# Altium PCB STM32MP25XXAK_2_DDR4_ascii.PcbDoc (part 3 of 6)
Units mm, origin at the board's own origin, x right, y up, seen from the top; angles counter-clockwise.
Board outline 120 x 79.6 mm, 4 copper layers (Top Layer, Signal Layer 1, Signal Layer 2, Bottom Layer), stack 1.614 mm thick; 243 components, 152 nets, 1304 pads, 784 vias.
Unrouted connection lines stored in the file: 6.

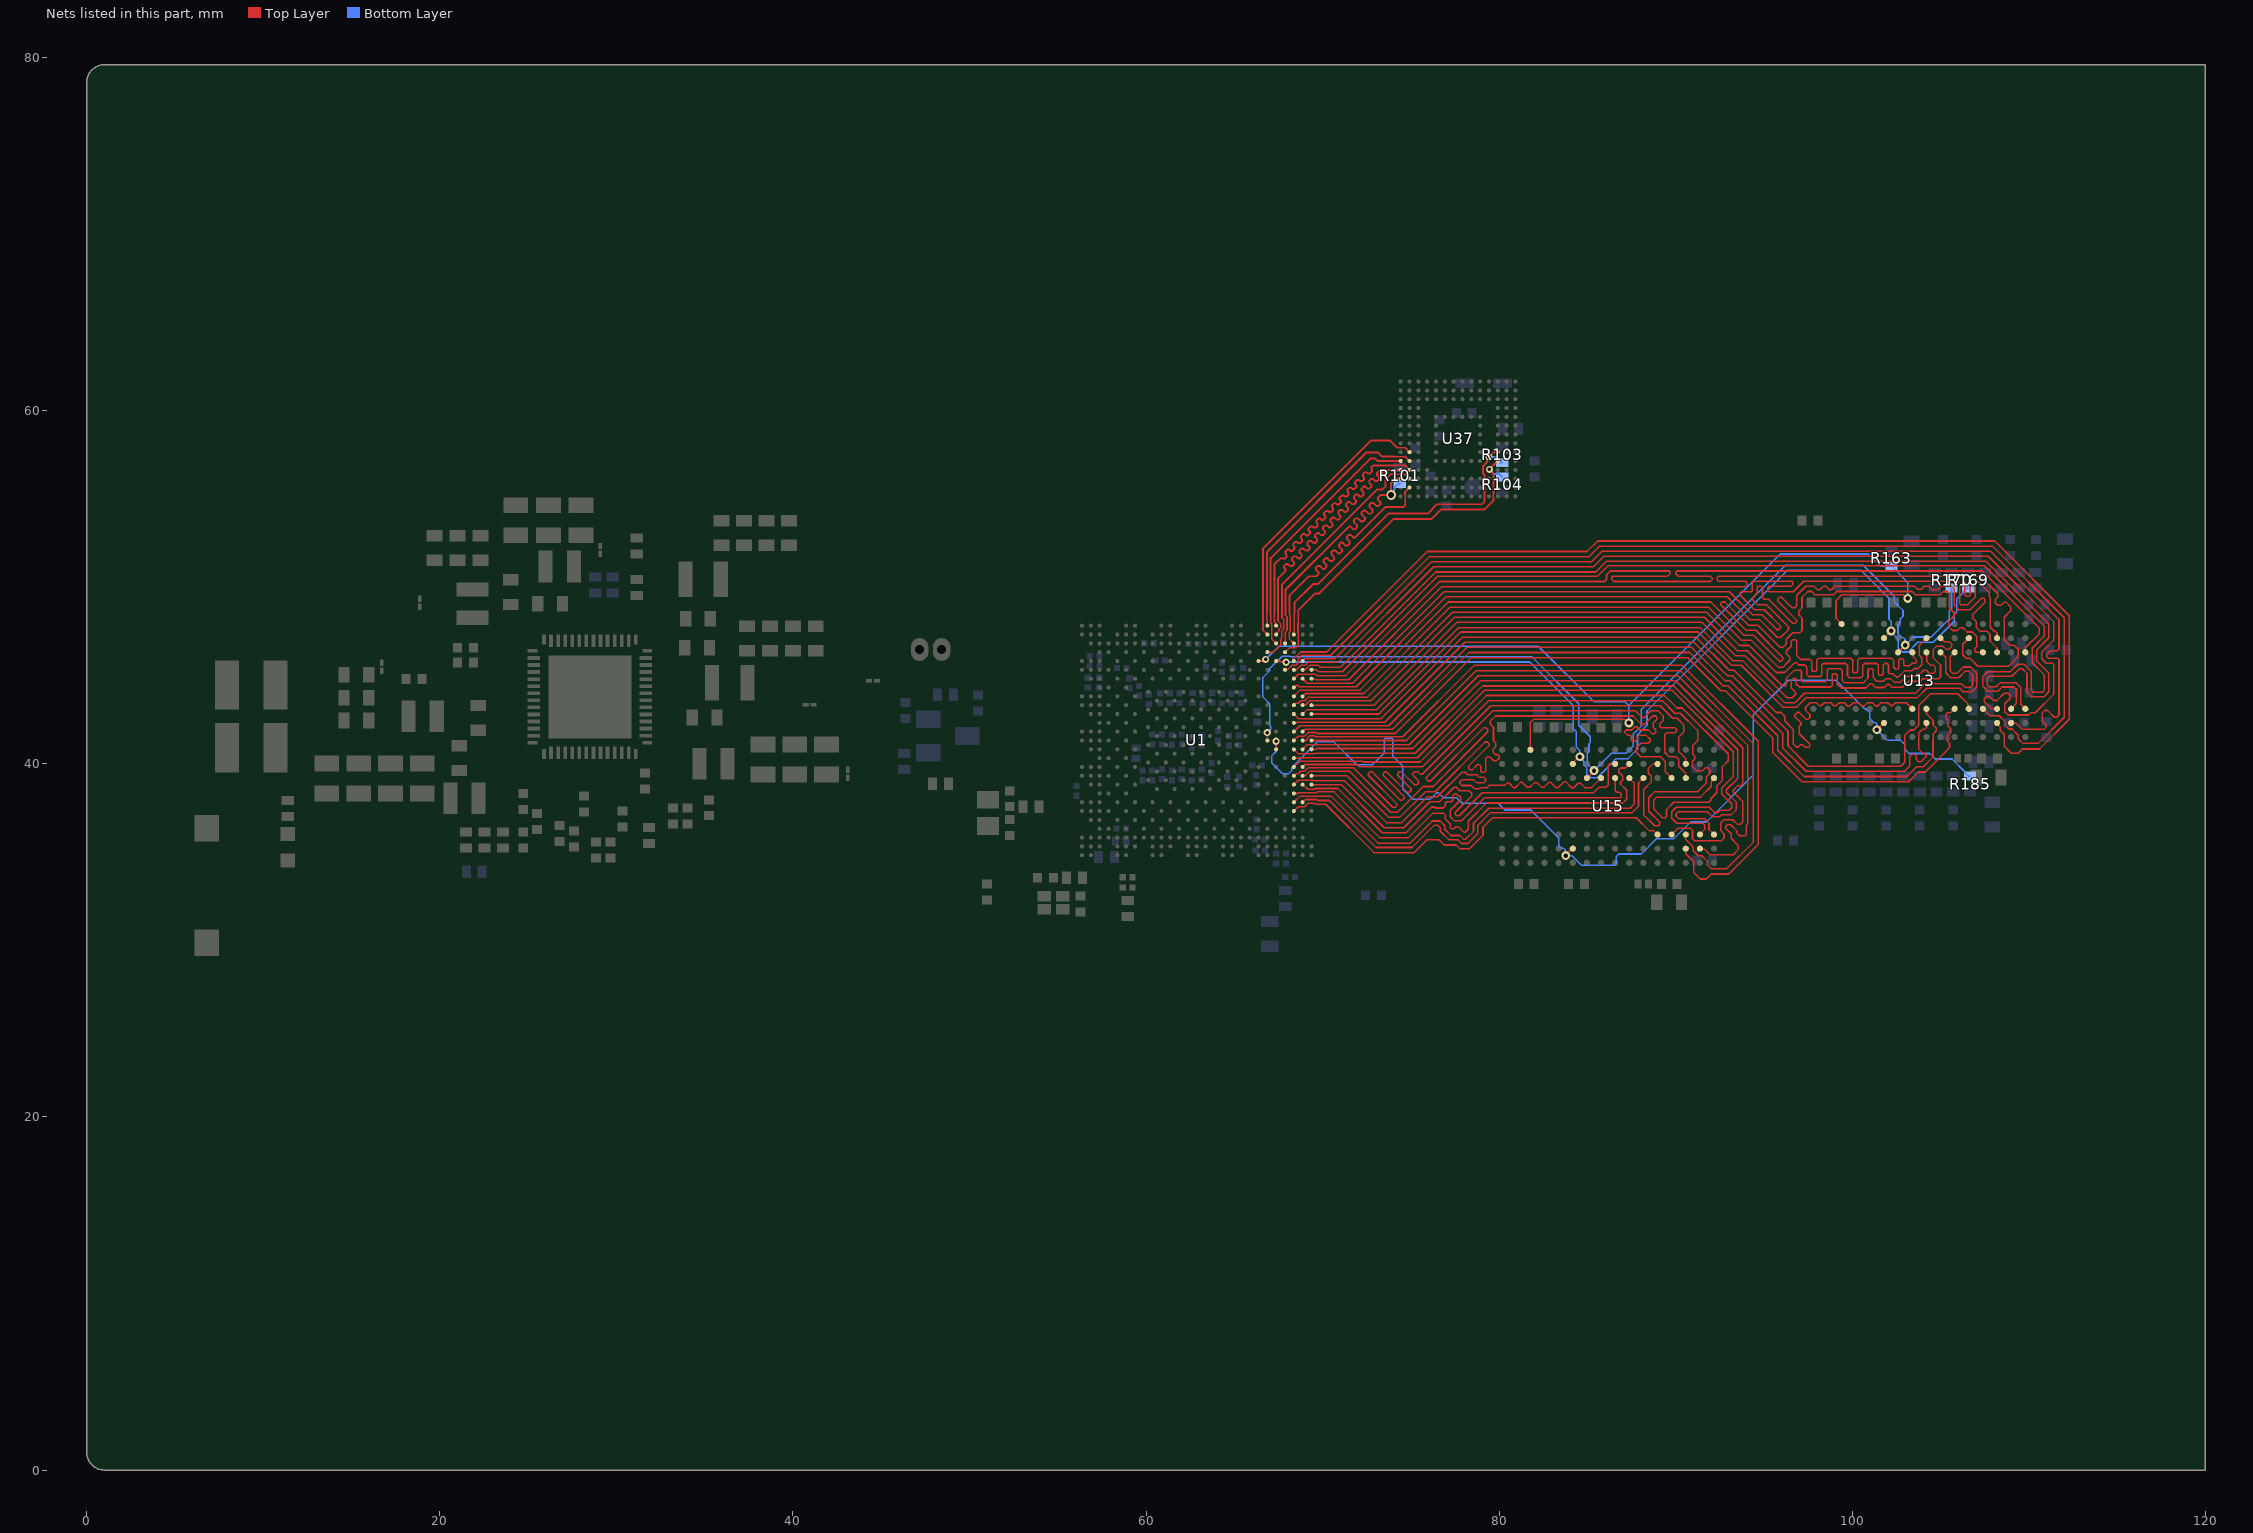
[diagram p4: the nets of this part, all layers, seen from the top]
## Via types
v1: diameter 0.55, hole 0.35, Top Layer to Bottom Layer, 256 vias
v2: diameter 0.4, hole 0.2, Top Layer to Bottom Layer, tented both sides, 235 vias
v3: diameter 0.5, hole 0.2, Top Layer to Bottom Layer, 146 vias
v4: diameter 0.5, hole 0.25, Top Layer to Bottom Layer, 143 vias
v5: diameter 0.5, hole 0.25, Top Layer to Bottom Layer, tented both sides, 4 vias

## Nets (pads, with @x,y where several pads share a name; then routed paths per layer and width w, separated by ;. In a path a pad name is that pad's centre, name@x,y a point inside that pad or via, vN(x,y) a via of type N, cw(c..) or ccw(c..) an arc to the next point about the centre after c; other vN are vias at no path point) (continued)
DDR_DQ4: U1.W25 U15.J3 | length 24.8
  Top Layer w0.09: U1.W25@68.375,38.825 68.625,39.075 69.479,39.075 69.503,39.05 71.246,39.05 73.622,36.674 74.485,36.674 75.948,38.137 76.504,38.137 77.893,39.527 78.085,39.527 78.231,39.381 78.741,39.381 78.891,39.231 79.151,39.231 79.229,39.153 79.229,39.006 79.164,38.941 78.725,38.941 78.576,39.09 77.892,39.09 77.783,38.981 77.783,38.887 77.896,38.773 78.424,38.773 78.613,38.585 78.857,38.585 78.923,38.651 79.303,38.651 79.431,38.779 80.319,38.779 80.443,38.904 80.569,38.904 80.82,38.653 80.918,38.653 81.214,38.949 81.317,38.949 81.592,38.674 81.737,38.674 81.984,38.921 82.159,38.921 82.397,38.683 82.548,38.683 82.813,38.949 82.932,38.949 83.23,38.651 83.338,38.651 83.665,38.978 83.792,38.978 84.119,38.651 84.234,38.651 84.487,38.904 84.616,38.904 84.862,38.658 85.235,38.658 U15.J3@85.774,39.197
DDR_DQ5: U1.W27 U15.H2 | length 23.8
  Top Layer w0.09: U1.W27@69.375,38.846 U1.W27@69.375,38.825 ; U1.W27@69.389,38.811 U1.W27@69.375,38.825 ; U15.H2@86.572,39.999 86.265,39.999 86.195,39.929 86.195,38.811 86.054,38.67 85.657,38.67 85.348,38.361 79.043,38.361 77.738,37.056 77.593,37.056 77.52,37.128 77.52,37.256 78.448,38.184 78.448,38.338 78.302,38.483 77.776,38.483 77.578,38.682 77.459,38.682 76.624,37.847 76.068,37.847 74.605,36.384 73.5,36.384 71.06,38.825 U1.W27@69.375,38.825
DDR_DQ6: U1.W26 U15.H3 | length 24.4
  Top Layer w0.09: U1.W26@68.875,38.825 68.899,38.825 69.163,38.561 69.529,38.561 69.573,38.605 70.87,38.605 73.38,36.094 74.725,36.094 76.188,37.557 76.341,37.557 76.397,37.501 76.839,37.501 76.95,37.611 76.95,37.763 77.034,37.848 77.285,37.848 77.381,37.943 77.381,38.191 77.48,38.29 77.559,38.29 77.656,38.193 77.75,38.193 77.828,38.116 77.828,37.974 77.23,37.376 77.23,37.008 77.472,36.766 77.858,36.766 79.163,38.071 86.867,38.071 86.92,38.124 86.92,38.285 86.818,38.388 86.664,38.388 86.573,38.478 U15.H3@86.573,39.196
DDR_DQ7: U1.Y25 U15.G2 | length 25.1
  Top Layer w0.09: U1.Y25@68.381,38.319 68.594,38.319 68.646,38.37 69.652,38.37 69.692,38.41 70.652,38.41 73.258,35.804 74.845,35.804 76.252,37.211 76.855,37.211 76.94,37.125 76.94,36.888 77.226,36.602 77.226,36.397 77.288,36.334 77.45,36.334 77.547,36.431 77.708,36.431 78.015,36.123 78.09,36.123 78.261,36.294 78.261,36.752 79.289,37.781 87.016,37.781 87.226,37.991 87.226,38.504 86.876,38.853 86.876,38.962 86.999,39.084 86.999,39.304 86.783,39.52 86.783,39.661 86.888,39.766 87.143,39.766 U15.G2@87.374,39.997
DDR_DQ8: U1.R27 U15.D7 | length 38.6
  Top Layer w0.09: U1.R27@69.375,40.825 69.378,40.828 69.625,40.828 69.669,40.872 75.114,40.872 78.946,44.704 89.629,44.704 90.014,44.704 93.806,40.913 93.806,38.866 93.689,38.749 93.499,38.749 93.26,38.51 93.26,38.412 93.806,37.866 93.806,36.709 93.666,36.569 93.511,36.569 93.243,36.837 92.739,36.837 92.552,36.65 92.552,36.218 92.739,36.032 92.739,35.792 92.598,35.652 91.053,35.652 90.954,35.751 90.954,36.248 90.861,36.342 90.119,36.342 U15.D7@89.774,35.997
DDR_DQ9: U1.R26 U15.B8 | length 39.3
  Top Layer w0.09: U1.R26@68.875,40.825 69.125,41.075 69.479,41.075 69.489,41.085 74.917,41.085 78.826,44.994 90.135,44.994 94.096,41.033 94.096,36.589 93.995,36.489 93.995,36.003 93.913,35.921 93.631,35.921 93.474,36.078 93.474,36.196 93.123,36.547 92.919,36.547 92.842,36.47 92.842,36.339 93.144,36.037 93.144,35.787 93.537,35.393 93.537,35.127 93.261,34.85 91.942,34.85 91.631,35.161 91.41,35.161 U15.B8@91.374,35.197
DDR_DQ10: U1.P27 U15.C7 | length 39.6
  Top Layer w0.09: U1.P27@69.375,41.325 74.747,41.325 78.706,45.284 90.255,45.284 94.386,41.153 94.386,35.551 92.886,34.052 92.031,34.052 91.782,34.301 91.782,34.503 91.487,34.797 91.286,34.797 91.001,35.082 91.001,35.294 90.58,35.715 90.58,35.991 U15.C7@90.574,35.997
DDR_DQ11: U1.P26 U15.C8 | length 41.4
  Top Layer w0.09: U1.P26@68.875,41.325 69.072,41.325 69.125,41.378 69.125,41.429 69.282,41.585 69.528,41.585 69.584,41.528 74.54,41.528 78.584,45.572 ; 78.584,45.574 90.375,45.574 94.676,41.273 94.676,35.431 93.006,33.762 92.015,33.762 91.732,33.479 91.393,33.479 91.027,33.845 91.027,34.459 90.574,34.911 U15.C8@90.574,35.197
DDR_DQ12: U1.V26 U15.C3 | length 39.6
  Top Layer w0.09: U1.V26@68.875,39.325 69.007,39.325 69.267,39.585 71.533,39.585 73.864,37.254 74.245,37.254 75.707,38.717 76.263,38.717 79.358,41.811 79.358,41.943 79.247,42.054 79.141,42.054 76.101,39.013 76.009,39.013 75.886,39.137 75.886,39.237 79.651,43.002 87.724,43.002 88.1,42.627 88.216,42.627 88.591,43.002 89.002,43.002 89.291,42.713 89.291,42.446 89.091,42.247 89.091,42.131 89.17,42.051 89.971,42.051 90.048,41.974 90.048,41.841 89.966,41.758 89.48,41.758 89.382,41.66 89.382,40.65 89.63,40.403 90.018,40.403 90.174,40.247 90.174,39.86 90.574,39.46 U15.C3@90.574,39.197
DDR_DQ13: U1.V27 U15.D3 | length 39.8
  Top Layer w0.09: U1.V27@69.385,39.335 U1.V27@69.375,39.325 71.383,39.325 73.744,36.964 74.365,36.964 75.828,38.427 76.384,38.427 79.197,41.24 79.329,41.24 79.432,41.137 79.432,41.033 78.274,39.875 78.274,39.748 78.347,39.675 78.498,39.675 78.77,39.946 78.889,39.946 78.95,39.885 78.95,39.581 79.011,39.521 79.174,39.521 79.252,39.599 79.252,40.308 79.334,40.391 79.478,40.391 79.696,40.173 79.859,40.173 80.003,40.316 80.003,40.458 79.932,40.528 79.777,40.528 79.667,40.638 79.667,40.845 79.806,40.983 79.806,41.187 79.682,41.311 79.682,42.08 79.489,42.273 79.489,42.408 79.794,42.712 87.589,42.712 88.072,42.228 88.228,42.228 88.711,42.712 88.882,42.712 88.935,42.659 88.935,42.517 88.722,42.304 88.722,42.076 88.874,41.924 88.874,41.789 88.801,41.717 88.659,41.717 88.459,41.917 87.97,41.917 87.793,42.094 87.689,42.094 87.642,42.048 cw(c87.354,42.317) 87.623,42.028 87.512,41.917 87.209,41.917 87.13,41.838 87.13,41.77 87.274,41.626 87.425,41.626 87.5,41.55 ; 87.5,41.553 87.5,41.55 ; U15.D3@89.772,39.197 89.405,39.563 89.405,40.137 89.145,40.397 88.021,40.397 87.766,40.653 87.766,40.908 88.024,41.166 88.449,41.166 88.555,41.273 88.555,41.401 88.344,41.612 87.931,41.612 87.827,41.507 87.827,41.381 87.719,41.274 87.575,41.274 87.5,41.348 87.5,41.55
DDR_DQ14: U1.V25 U15.C2 | length 39.8
  Top Layer w0.09: U1.V25@68.375,39.325 68.5,39.45 68.646,39.45 68.771,39.575 68.979,39.575 69.179,39.775 71.753,39.775 73.984,37.544 74.12,37.544 74.212,37.637 74.212,37.732 72.593,39.352 72.593,39.444 72.693,39.543 72.812,39.543 74.407,37.948 74.524,37.948 74.631,38.055 74.631,38.152 73.446,39.337 73.446,39.462 73.527,39.543 73.642,39.543 74.809,38.377 74.918,38.377 75.012,38.471 75.012,38.595 74.258,39.349 74.258,39.463 74.339,39.543 74.479,39.543 75.211,38.812 75.347,38.812 75.429,38.894 75.429,39.037 75.119,39.347 75.119,39.468 75.195,39.543 75.408,39.543 75.544,39.407 75.643,39.407 79.528,43.292 89.122,43.292 89.832,42.582 90.084,42.582 90.464,42.202 90.464,41.809 90.179,41.523 90.179,40.704 90.574,40.309 U15.C2@90.574,39.997
DDR_DQ15: U1.U25 U15.A3 | length 39.4
  Top Layer w0.09: U1.U25@68.375,39.825 68.705,40.155 72.246,40.155 72.298,40.103 75.519,40.103 79.288,43.872 89.362,43.872 90.072,43.162 90.383,43.162 92.976,40.569 92.976,40.177 92.649,39.85 92.649,39.073 92.325,38.749 92.325,38.366 91.985,38.025 91.985,37.935 91.879,37.829 89.897,37.829 89.483,37.415 89.483,37.025 89.406,36.948 89.258,36.948 88.77,37.436 88.77,37.963 88.926,38.119 91.412,38.119 92.024,38.731 92.024,38.989 92.174,39.139 U15.A3@92.174,39.197
DDR_DQ16: U1.F25 U13.C7 | length 59.4
  Top Layer w0.09: U1.F25@68.375,45.325 68.521,45.325 68.771,45.575 69.017,45.575 69.208,45.766 70.9,45.766 76.293,51.159 85.352,51.159 85.948,51.755 107.709,51.755 111.428,48.036 111.428,47.018 110.742,46.332 110.742,45.948 110.988,45.701 111.343,45.701 111.428,45.615 111.428,43.96 110.363,42.895 110.132,42.895 110.004,42.768 108.824,42.768 108.641,42.951 108.641,43.403 108.959,43.721 108.959,43.865 108.826,43.998 108.612,43.998 108.204,43.59 107.984,43.59 107.758,43.816 107.602,43.816 107.473,43.688 107.473,43.54 107.893,43.12 U13.C7@108.205,43.12
DDR_DQ17: U1.E26 U13.B8 | length 57.9
  Top Layer w0.09: U1.E26@68.875,45.825 69.006,45.956 70.68,45.956 76.173,51.449 85.232,51.449 85.828,52.045 107.829,52.045 111.718,48.156 111.718,46.503 111.618,46.403 111.223,46.403 111.032,46.212 111.032,46.068 111.108,45.991 111.636,45.991 111.718,45.909 111.718,42.769 111.59,42.641 111.447,42.641 111.067,43.021 110.898,43.021 110.763,42.886 110.763,42.433 111.003,42.193 111.003,42.093 110.859,41.949 109.622,41.949 109.275,42.296 109.029,42.296 U13.B8@109.005,42.32
DDR_DQ18: U1.F24 U13.D7 | length 60.7
  Top Layer w0.09: U1.F24@67.876,45.326 68.013,45.326 68.262,45.575 68.479,45.575 68.625,45.721 68.625,45.929 68.842,46.146 70.46,46.146 76.053,51.739 85.112,51.739 85.707,52.335 107.949,52.335 112.008,48.276 112.008,42.644 110.523,41.159 109.678,41.159 109.411,41.426 109.411,41.624 109.06,41.975 108.862,41.975 108.66,42.177 108.66,42.394 108.333,42.722 107.803,42.722 U13.D7@107.405,43.12
DDR_DQ19: U1.E25 U13.C8 | length 60.6
  Top Layer w0.09: U1.E25@68.375,45.825 68.375,45.996 68.464,46.085 68.519,46.085 68.772,46.338 70.242,46.338 75.933,52.029 84.986,52.029 85.582,52.625 108.069,52.625 112.298,48.396 112.298,42.524 110.614,40.84 109.638,40.84 109.403,40.605 109.344,40.605 109.017,40.605 108.611,41.011 108.611,41.673 108.379,41.905 108.379,42.103 108.205,42.277 U13.C8@108.205,42.32
DDR_DQ20: U1.J25 U13.D3 | length 58.9
  Top Layer w0.09: U1.J25@68.375,43.825 68.727,44.177 72.125,44.177 77.118,49.169 91.978,49.169 91.981,49.167 91.984,49.167 93.869,47.282 94.414,47.282 95.873,45.822 95.981,45.822 96.06,45.902 96.06,46.046 94.534,47.572 93.99,47.572 92.554,49.007 92.554,49.097 92.626,49.169 92.802,49.169 94.11,47.862 94.654,47.862 95.918,46.598 96.078,46.598 96.265,46.785 96.265,47.062 96.636,47.433 97.051,47.433 97.158,47.541 97.158,48.256 96.969,48.445 96.969,48.642 97.158,48.831 97.158,49.427 97.496,49.765 97.716,49.765 97.91,49.571 98.935,49.571 99.129,49.765 103.409,49.765 103.591,49.583 104.973,49.583 105.155,49.765 105.4,49.765 105.503,49.661 105.503,48.838 105.775,48.566 105.775,48.382 105.46,48.067 105.46,48.063 105.46,47.777 105.683,47.554 105.96,47.554 106.111,47.704 106.268,47.704 106.502,47.47 106.804,47.47 107.057,47.217 107.057,46.649 106.94,46.532 106.94,46.406 107.026,46.32 U13.D3@107.405,46.32
DDR_DQ21: U1.H25 U13.C3 | length 59.1
  Top Layer w0.09: U1.H25@68.375,44.327 68.485,44.438 68.62,44.438 68.688,44.37 71.908,44.37 76.998,49.459 92.922,49.459 93.311,49.07 93.321,49.06 94.23,48.152 94.775,48.152 95.761,47.165 95.958,47.165 96.394,47.601 96.394,47.763 95.135,49.022 94.631,49.022 94.38,49.273 94.38,49.441 94.629,49.69 94.629,50.002 94.682,50.055 94.836,50.055 94.92,49.971 94.92,49.418 95.019,49.319 95.261,49.319 96.621,47.959 96.751,47.959 96.85,48.058 96.85,48.154 95.784,49.22 95.784,49.332 95.88,49.427 96.006,49.427 96.586,48.847 96.764,48.847 96.868,48.952 96.868,49.547 97.376,50.055 97.836,50.055 98.03,49.861 98.181,49.861 98.375,50.055 98.513,50.055 98.707,49.861 98.815,49.861 99.009,50.055 103.532,50.055 103.698,49.889 103.922,49.889 104.089,50.055 104.328,50.055 104.51,49.873 104.853,49.873 105.035,50.055 105.625,50.055 105.793,49.886 105.793,48.968 106.036,48.725 106.669,48.725 107.326,49.382 107.447,49.382 107.516,49.313 107.516,49.144 106.84,48.468 106.84,48.249 107.017,48.072 107.017,47.73 107.242,47.505 107.641,47.505 107.806,47.341 107.806,46.963 108.205,46.563 U13.C3@108.205,46.32
DDR_DQ22: U1.G26 U13.C2 | length 56.9
  Top Layer w0.09: U1.G26@68.875,44.825 69.134,44.566 71.694,44.566 76.877,49.749 93.042,49.749 94.35,48.442 94.895,48.442 95.725,47.611 95.84,47.611 95.942,47.712 95.942,47.805 95.015,48.732 94.47,48.732 93.629,49.573 93.629,49.672 93.706,49.749 94.279,49.749 94.339,49.81 94.339,50.258 94.427,50.345 96.58,50.345 96.633,50.292 96.633,50.153 96.529,50.049 95.287,50.049 95.21,49.972 95.21,49.838 95.299,49.749 96.66,49.749 97.256,50.345 105.954,50.345 106.083,50.215 106.083,49.088 106.156,49.015 106.538,49.015 106.972,49.449 106.972,50.22 107.058,50.307 107.163,50.307 107.734,49.736 107.76,49.71 107.76,49.479 107.819,49.421 ; 107.817,49.421 107.817,47.739 108.049,47.508 108.11,47.508 108.206,47.412 U13.C2@108.206,47.1
DDR_DQ23: U1.G25 U13.A3 | length 59.5
  Top Layer w0.09: U1.G25@68.375,44.825 68.625,45.075 69.588,45.075 69.664,44.999 71.306,44.999 76.637,50.329 85.98,50.329 86.086,50.436 86.086,50.719 86.292,50.925 89.647,50.925 89.7,50.872 89.7,50.779 89.545,50.625 86.433,50.625 86.38,50.572 86.38,50.438 86.488,50.329 91.977,50.329 92.066,50.419 92.066,50.526 91.964,50.628 90.143,50.628 90.005,50.766 90.005,50.872 90.058,50.925 107.365,50.925 110.598,47.693 110.598,47.362 109.805,46.569 U13.A3@109.805,46.32
DDR_DQ24: U1.J26 U13.J3 | length 45.3
  Top Layer w0.09: U1.J26@68.875,43.825 69.037,43.987 72.345,43.987 77.238,48.879 91.858,48.879 91.861,48.877 91.864,48.877 93.749,46.992 94.294,46.992 95.821,45.464 96.064,45.464 96.466,45.866 96.466,46.05 96.27,46.246 96.27,46.381 96.555,46.665 96.555,46.942 96.647,47.034 96.795,47.034 96.858,46.971 96.858,46.136 97.085,45.909 97.621,45.909 97.708,45.822 97.708,45.302 97.761,45.25 97.945,45.25 97.998,45.302 97.998,45.877 98.096,45.975 99.918,45.975 100.028,45.865 100.028,45.23 100.093,45.165 100.24,45.165 100.318,45.243 100.318,45.877 100.416,45.975 102.228,45.975 102.348,45.855 102.348,45.472 102.465,45.356 102.562,45.356 102.638,45.432 102.638,45.897 102.705,45.964 102.851,45.964 102.928,45.887 102.928,45.609 102.984,45.553 103.251,45.553 103.396,45.698 103.587,45.698 103.64,45.751 103.64,45.881 103.45,46.071 103.45,46.275 U13.J3@103.405,46.32
DDR_DQ25: U1.K25 U13.H2 | length 45.7
  Top Layer w0.09: U1.K25@68.375,43.325 68.489,43.439 68.628,43.439 68.764,43.575 68.995,43.575 69.204,43.784 72.553,43.784 77.358,48.589 91.738,48.589 91.74,48.587 91.744,48.587 93.621,46.71 ; 93.635,46.702 94.174,46.702 95.701,45.174 96.184,45.174 96.734,45.723 96.851,45.723 96.969,45.606 ; 96.969,45.601 97.311,45.601 97.418,45.494 97.418,45.064 97.535,44.948 98.224,44.948 98.288,45.011 98.288,45.604 98.369,45.685 99.642,45.685 99.738,45.589 99.738,44.99 99.853,44.875 100.493,44.875 100.608,44.99 100.608,45.597 100.696,45.685 101.411,45.685 101.478,45.618 101.478,45.085 101.553,45.01 101.676,45.01 101.768,45.103 101.768,45.617 101.836,45.685 101.986,45.685 102.058,45.613 102.058,45.163 102.121,45.1 102.316,45.1 102.496,44.92 102.615,44.92 102.958,45.263 103.382,45.263 103.521,45.401 103.731,45.401 103.939,45.61 103.939,46.017 103.81,46.146 103.81,46.725 U13.H2@104.205,47.12
DDR_DQ26: U1.K26 U13.H3 | length 45.1
  Top Layer w0.09: U1.K26@68.875,43.325 69.015,43.325 69.272,43.582 72.761,43.582 77.478,48.299 91.618,48.299 91.62,48.297 91.624,48.297 93.509,46.412 94.053,46.412 96.07,44.395 96.18,44.395 96.257,44.473 96.257,44.837 96.732,45.311 97.053,45.311 97.128,45.237 97.128,44.72 97.192,44.657 98.469,44.657 98.578,44.765 98.578,45.306 98.667,45.395 99.347,45.395 99.448,45.294 99.448,44.714 99.577,44.585 100.626,44.585 100.898,44.857 100.898,45.326 100.967,45.395 101.111,45.395 101.188,45.318 101.188,44.886 101.396,44.678 101.753,44.678 101.819,44.744 101.886,44.81 102.191,44.81 102.196,44.81 102.376,44.63 102.736,44.63 103.078,44.973 103.502,44.973 103.641,45.111 103.851,45.111 104.047,45.308 104.2,45.308 104.368,45.14 104.63,45.14 104.716,45.225 104.716,45.482 104.605,45.593 104.427,45.593 104.229,45.791 104.229,46.296 U13.H3@104.205,46.32
DDR_DQ27: U1.K27 U13.G2 | length 46.7
  Top Layer w0.09: U1.K27@69.375,43.325 72.914,43.325 77.598,48.009 91.498,48.009 91.5,48.007 91.503,48.007 93.389,46.122 93.933,46.122 96.312,43.743 96.608,43.743 96.801,43.936 96.801,44.047 96.547,44.301 96.547,44.717 96.678,44.847 96.772,44.847 96.838,44.781 96.838,44.512 96.998,44.351 98.771,44.351 98.868,44.448 98.868,45.019 98.954,45.105 99.065,45.105 99.158,45.012 99.158,44.512 99.375,44.295 100.763,44.295 100.996,44.529 101.135,44.529 101.338,44.325 101.811,44.325 101.981,44.496 102.1,44.496 102.267,44.328 102.844,44.328 103.198,44.683 103.859,44.683 103.997,44.821 104.908,44.821 105.006,44.919 105.006,45.602 104.583,46.025 104.583,46.473 104.775,46.665 105.149,46.665 105.315,46.499 105.496,46.499 105.647,46.65 105.647,46.785 105.519,46.914 105.217,46.914 105.011,47.12 U13.G2@105.005,47.12
DDR_DQ28: U1.L25 U13.J7 | length 45.8
  Top Layer w0.09: U1.L25@68.375,42.821 68.642,42.553 73.316,42.553 77.942,47.179 91.154,47.179 91.156,47.177 91.16,47.177 93.034,45.303 93.04,45.303 93.051,45.292 93.321,45.292 95.705,42.908 95.975,42.908 96.18,42.703 96.18,42.437 96.178,42.435 96.653,41.96 96.653,41.138 96.838,40.954 96.949,40.954 97.079,41.084 97.183,41.084 97.338,40.929 97.555,40.929 97.607,40.982 97.607,41.106 97.008,41.706 97.008,42.125 97.103,42.221 97.103,42.331 96.752,42.682 96.752,42.775 96.888,42.911 96.995,42.911 97.381,42.525 97.496,42.525 97.61,42.64 97.61,42.774 97.357,43.027 97.357,43.202 97.62,43.465 97.978,43.465 98.147,43.296 98.249,43.296 98.418,43.465 98.781,43.465 98.954,43.292 99.089,43.292 99.262,43.465 99.548,43.465 99.75,43.263 99.75,43.26 99.852,43.26 100.057,43.465 100.354,43.465 100.542,43.277 100.674,43.277 100.862,43.465 101.148,43.465 101.249,43.364 ; 101.25,43.365 101.338,43.277 101.454,43.277 101.642,43.465 102.022,43.465 102.18,43.307 102.286,43.307 102.444,43.465 103.066,43.465 U13.J7@103.406,43.125
DDR_DQ29: U1.N25 U13.H8 | length 44.7
  Top Layer w0.09: U1.N25@68.375,41.825 68.712,42.162 73.745,42.162 78.182,46.599 90.914,46.599 90.916,46.597 90.919,46.597 92.794,44.723 92.8,44.723 92.811,44.712 93.081,44.712 96.073,41.719 96.073,40.898 97.397,39.574 102.96,39.574 103.267,39.881 103.267,40.419 103.393,40.545 103.534,40.545 103.618,40.46 103.618,40.259 103.76,40.117 103.902,40.117 104.201,40.415 104.201,40.513 104.134,40.58 104.017,40.58 103.781,40.816 103.781,41.762 103.971,41.952 104.123,41.952 104.209,42.038 104.209,42.316 U13.H8@104.205,42.32
DDR_DQ30: U1.N26 U13.H7 | length 44.5
  Top Layer w0.09: U1.N26@68.875,41.825 69.017,41.967 73.96,41.967 78.302,46.309 90.794,46.309 90.796,46.307 90.799,46.307 92.674,44.433 92.68,44.433 92.691,44.422 92.961,44.422 95.783,41.599 95.783,40.778 97.277,39.284 97.486,39.284 103.091,39.284 103.635,39.827 104.022,39.827 104.581,40.385 104.581,41.341 104.601,41.361 104.601,41.711 104.767,41.878 104.767,42.026 104.581,42.213 104.581,42.467 104.21,42.838 104.21,43.115 U13.H7@104.205,43.12
DDR_DQ31: U1.P25 U13.F7 | length 46
  Top Layer w0.09: U1.P25@68.375,41.325 68.625,41.575 68.995,41.575 69.195,41.775 69.606,41.775 69.663,41.718 74.121,41.718 78.422,46.019 90.674,46.019 90.676,46.017 90.679,46.017 92.553,44.143 92.559,44.143 92.571,44.132 92.841,44.132 95.493,41.479 95.493,40.658 97.157,38.994 103.212,38.994 103.755,39.537 104.146,39.537 105.516,40.906 105.516,41.159 105.401,41.274 105.401,41.604 105.57,41.773 105.57,42.002 105.411,42.161 105.411,42.498 105.331,42.578 105.331,42.822 105.415,42.906 105.591,42.906 U13.F7@105.805,43.12
DDR_DQM0: U1.AB25 U15.E7 | length 23.9
  Top Layer w0.09: U1.AB25@68.375,37.325 68.625,37.575 68.988,37.575 69.193,37.78 69.562,37.78 69.635,37.706 70.181,37.706 72.913,34.974 75.189,34.974 75.927,35.713 76.589,35.713 76.901,35.401 77.559,35.401 77.76,35.2 78.34,35.2 79.091,35.95 79.091,36.409 79.633,36.951 87.771,36.951 88.521,36.201 88.77,36.201 U15.E7@88.974,35.997
DDR_DQM1: U1.U26 U15.E2 | length 39.1
  Top Layer w0.09: U1.U26@68.875,39.832 69.008,39.965 71.973,39.965 72.105,39.833 75.659,39.833 79.408,43.582 89.242,43.582 89.952,42.872 90.262,42.872 91.242,41.893 91.242,41.306 90.976,41.039 90.976,40.56 91.086,40.45 91.086,40.257 90.942,40.113 90.942,39.853 91.178,39.617 91.518,39.617 91.687,39.786 91.82,39.786 91.946,39.66 91.946,39.468 91.734,39.256 91.734,38.917 91.226,38.409 88.806,38.409 88.48,38.083 88.48,37.315 89.095,36.7 89.095,36.573 89.01,36.488 88.81,36.488 88.19,37.108 88.19,38.55 88.608,38.968 88.608,39.321 88.456,39.473 88.456,39.732 88.721,39.997 U15.E2@88.974,39.997
DDR_DQM2: U1.G27 U13.E2 | length 57.2
  Top Layer w0.09: U1.G27@69.375,44.825 69.544,44.825 69.598,44.772 71.489,44.772 76.757,50.039 93.952,50.039 94.049,50.136 94.049,50.264 93.97,50.343 92.429,50.343 92.356,50.415 92.356,50.554 92.438,50.635 106.259,50.635 106.378,50.516 106.378,49.579 106.471,49.485 106.598,49.485 106.682,49.569 106.682,50.54 106.776,50.635 107.245,50.635 108.251,49.629 108.251,49.45 108.109,49.308 108.109,49.126 108.244,48.991 108.433,48.991 108.586,49.144 108.736,49.144 108.99,48.891 108.99,48.687 108.61,48.308 108.61,47.027 108.917,46.72 109.169,46.72 109.401,46.489 109.401,46.085 108.85,45.534 107.115,45.534 106.674,45.975 106.462,45.975 106.26,46.177 106.26,46.77 U13.E2@106.605,47.115
DDR_DQM3: U1.M25 U13.E7 | length 47.2
  Top Layer w0.09: U1.M25@68.375,42.325 68.544,42.325 68.571,42.352 69.081,42.352 73.525,42.352 78.062,46.889 91.034,46.889 91.036,46.887 91.039,46.887 92.914,45.013 92.92,45.013 92.931,45.002 93.201,45.002 96.363,41.84 96.363,41.018 97.518,39.864 102.746,39.864 102.977,40.095 102.977,41.6 103.296,41.92 103.493,41.92 103.783,42.21 103.783,43.326 104.432,43.975 105.983,43.975 106.546,43.413 106.546,43.179 U13.E7@106.605,43.12
DDR_DQS0_N: U1.AA26 U15.F3 | length 24.1
  Top Layer w0.09: U1.AA26@68.875,37.825 69.029,37.979 69.677,37.979 69.732,37.924 70.373,37.924 73.033,35.264 75.069,35.264 76.319,36.514 76.55,36.514 76.673,36.392 76.673,36.186 77.168,35.691 77.679,35.691 77.88,35.49 78.22,35.49 78.801,36.07 78.801,36.529 79.513,37.241 87.536,37.241 87.898,37.603 87.898,38.921 U15.F3@88.174,39.197
DDR_DQS0_P: U1.AA25 U15.G3 | length 24.3
  Top Layer w0.09: U1.AA25@68.375,37.825 68.724,38.174 70.477,38.174 73.138,35.514 74.965,35.514 76.215,36.764 76.654,36.764 76.924,36.495 76.924,36.289 77.271,35.941 77.783,35.941 77.984,35.74 78.116,35.74 78.551,36.174 78.551,36.632 79.409,37.491 87.432,37.491 87.648,37.707 87.648,38.916 87.374,39.19 U15.G3@87.374,39.197
DDR_DQS1_N: U1.R25 U15.A7 | length 38.9
  Top Layer w0.09: U1.R25@68.375,40.825 68.639,40.561 69.532,40.561 69.574,40.604 75.256,40.604 79.064,44.412 89.897,44.412 93.516,40.793 93.516,39.176 92.865,38.526 92.865,38.396 93.423,37.839 93.423,37.392 93.158,37.127 92.619,37.127 92.485,36.993 92.094,36.993 91.8,37.287 90.133,37.287 90.023,37.178 90.023,37.026 90.16,36.889 91.647,36.889 91.89,36.646 91.89,36.281 U15.A7@92.174,35.997
DDR_DQS1_P: U1.T25 U15.B7 | length 38.4
  Top Layer w0.09: U1.T25@68.375,40.325 68.61,40.325 68.638,40.353 75.359,40.353 79.168,44.162 89.793,44.162 93.266,40.689 93.266,39.279 92.615,38.629 92.615,38.293 93.173,37.735 93.173,37.515 93.035,37.377 92.515,37.377 92.382,37.243 92.198,37.243 91.904,37.537 90.029,37.537 89.773,37.281 89.773,36.923 90.057,36.639 91.543,36.639 91.64,36.542 91.64,36.277 U15.B7@91.362,35.999
DDR_DQS2_N: U1.F26 U13.A7 | length 59.7
  Top Layer w0.09: U1.F26@68.875,45.325 69.021,45.325 69.271,45.575 69.769,45.575 69.875,45.469 71.013,45.469 76.414,50.869 85.472,50.869 86.068,51.465 107.589,51.465 111.138,47.916 111.138,47.138 110.452,46.452 110.452,45.827 111.138,45.141 111.138,44.081 110.865,43.807 110.155,43.807 109.905,44.058 109.905,45.118 109.628,45.395 109.478,45.395 109.045,44.962 107.758,44.962 107.658,44.862 107.658,44.492 107.789,44.361 108.163,44.361 108.405,44.603 109.266,44.603 109.542,44.328 109.542,43.383 U13.A7@109.805,43.12
DDR_DQS2_P: U1.F27 U13.B7 | length 58.7
  Top Layer w0.09: U1.F27@69.375,45.325 69.664,45.325 69.77,45.219 71.116,45.219 76.517,50.619 85.576,50.619 86.171,51.215 107.485,51.215 110.888,47.813 110.888,47.241 110.202,46.555 110.202,45.724 110.888,45.037 110.888,44.184 110.761,44.057 110.259,44.057 110.155,44.161 110.155,45.221 109.732,45.645 109.374,45.645 108.942,45.212 107.654,45.212 107.408,44.966 107.408,44.389 107.685,44.111 108.266,44.111 108.508,44.353 109.163,44.353 109.292,44.224 109.292,43.414 U13.B7@109.005,43.127
DDR_DQS3_N: U1.L27 U13.F3 | length 45.8
  Top Layer w0.09: U1.L27@69.375,42.825 69.376,42.824 73.176,42.824 77.822,47.469 91.274,47.469 91.277,47.467 91.28,47.467 93.165,45.582 93.71,45.582 96.088,43.203 96.844,43.203 97.396,43.755 103.695,43.755 104.221,44.281 106.087,44.281 106.282,44.087 106.787,44.087 107.066,44.365 107.066,45.134 106.716,45.484 106.29,45.484 105.94,45.134 105.68,45.134 105.546,45.268 105.546,46.061 U13.F3@105.805,46.32
DDR_DQS3_P: U1.L26 U13.G3 | length 46
  Top Layer w0.09: U1.L26@68.875,42.825 69.125,43.075 69.479,43.075 69.48,43.074 73.073,43.074 77.718,47.719 91.378,47.719 91.38,47.717 91.383,47.717 93.269,45.832 93.813,45.832 96.192,43.453 96.74,43.453 97.292,44.005 103.591,44.005 104.118,44.531 106.191,44.531 106.386,44.337 106.684,44.337 106.816,44.469 106.816,45.031 106.613,45.234 106.393,45.234 106.044,44.884 105.576,44.884 105.296,45.165 105.296,46.035 U13.G3@105.006,46.325
DDR_ODT: R170.1 U1.P22 U13.K3 U15.K3 | length 60.6
  Top Layer w0.09: v2(66.868,41.766) 66.875,41.759 U1.P22@66.875,41.325 ; U15.K3@84.974,39.197 84.988,39.197 85.381,39.589 v4@85.381,39.623 ; U13.K3@102.605,46.32 103.003,46.718 v4(103.003,46.729) ; v4@103.006,46.686 v4@103.006,46.725
  Bottom Layer w0.09: v2(66.868,41.766) 66.912,41.81 67.068,41.966 67.068,42.118 67.021,42.165 67.021,43.384 66.622,43.783 66.622,44.891 66.997,45.266 66.997,45.382 67.715,46.1 68.161,46.1 68.203,46.058 81.863,46.058 84.513,43.408 84.513,42.191 85.166,41.537 85.166,41.206 85.091,41.131 85.091,40.676 84.983,40.568 84.983,40.026 85.375,39.634 v4@85.375,39.616 ; v4@85.382,39.615 86.356,40.589 87.181,40.589 87.591,40.998 87.591,41.673 88.063,42.145 88.063,43.09 96.223,51.25 100.623,51.25 102.378,49.496 102.378,49.187 102.878,48.687 102.878,48.359 102.713,48.194 102.713,48.004 102.598,47.889 102.598,47.375 102.839,47.134 102.933,47.134 103.003,47.064 v4(103.003,46.729) ; v4@103.008,46.723 103.469,47.184 104.476,47.184 105.488,48.195 105.488,48.638 105.628,48.778 R170.1@105.628,49.952 R170.1@105.628,49.954
  other v4: 85.375,39.615
DDR_RASN: R185.1 U1.R23 U13.L8 U15.L8 | length 59.6
  Top Layer w0.09: U1.R23@67.375,40.825 v2(67.375,41.28) v2@67.375,41.289 ; v4@83.781,34.83 U15.L8@84.15,35.199 ; v4@101.405,41.926 U13.L8@101.802,42.323
  Bottom Layer w0.09: v2@67.375,41.289 v2(67.375,41.28) 67.375,40.708 67.115,40.448 67.115,40.066 67.749,39.431 67.781,39.431 67.783,39.43 68.068,39.43 68.256,39.618 68.256,39.79 69.728,41.262 70.615,41.262 71.931,39.946 72.829,39.946 73.493,40.61 73.493,41.376 73.571,41.453 73.921,41.453 73.988,41.386 73.988,40.435 74.535,39.888 74.535,38.584 75.132,37.987 76.085,37.987 76.211,38.112 76.452,38.353 76.574,38.353 76.848,38.079 77.59,38.079 77.907,37.762 79.946,37.762 80.322,37.386 81.792,37.386 83.382,35.796 83.382,35.368 83.541,35.209 83.673,35.209 83.753,35.129 83.753,34.829 v4(83.778,34.804) 84.113,34.804 84.668,34.249 86.516,34.249 86.643,34.376 86.643,34.755 86.781,34.894 88.061,34.894 88.936,35.769 89.91,35.769 90.848,36.708 91.742,36.708 94.388,39.353 94.388,42.754 96.373,44.739 99.085,44.739 100.7,43.124 100.763,43.124 ; 100.764,43.126 101.007,42.884 101.007,42.559 101.231,42.334 101.348,42.334 101.403,42.279 v4(101.403,41.929) 102.004,41.328 102.757,41.328 102.973,41.112 102.973,40.825 103.214,40.584 104.404,40.584 104.712,40.276 105.655,40.276 106.373,39.558 106.373,39.512 106.583,39.302 R185.1@106.678,39.302
DDR_RESETN: R163.2 U1.E21 U13.P1 U15.P1 | length 57.5
  Top Layer w0.09: U1.E21@66.375,45.825 66.601,45.825 ; U15.P1@81.774,40.797 81.774,42.349 81.946,42.521 87.149,42.521 v4(87.354,42.317) v4@87.204,42.317 ; U13.P1@99.406,47.925 99.082,48.248 99.082,49.246 99.411,49.575 102.886,49.575 103.043,49.418 v4@103.143,49.418
  Bottom Layer w0.09: v2@66.78,45.92 67.528,46.668 82.224,46.668 85.362,43.529 87.119,43.529 87.354,43.294 v4(87.354,42.317) ; 87.347,43.3 95.931,51.884 100.928,51.884 101.61,51.202 102.223,51.202 103.151,50.275 103.151,49.426 v4@103.143,49.418
  other v2: 66.779,45.921
  other v4: 103.143,49.37
DDR_WEN: R169.1 U1.E23 U13.L2 U15.L2 | length 56.1
  Top Layer w0.09: U1.E23@67.375,45.825 67.567,45.825 67.611,45.781 v2@67.941,45.781 ; U15.L2@84.174,39.997 84.174,40.045 v4@84.529,40.4 ; U13.L2@101.806,47.132 v4(102.203,47.529)
  Bottom Layer w0.09: v2@67.944,45.768 81.743,45.768 84.2,43.311 84.2,42.005 84.37,41.835 84.37,40.953 84.578,40.746 v4(84.578,40.404) 84.578,40.364 84.793,40.149 84.793,39.948 84.975,39.765 84.975,39.456 85.211,39.22 85.564,39.22 86.643,40.299 87.301,40.299 87.838,40.836 87.838,41.648 88.38,42.189 88.38,42.997 96.343,50.96 100.503,50.96 102.088,49.375 102.088,48.195 102.203,48.081 v4(102.203,47.529) ; v4@102.207,47.529 102.207,47.466 102.601,47.071 102.601,46.572 102.839,46.334 103.166,46.334 103.721,46.889 104.591,46.889 105.778,48.075 105.778,48.463 105.918,48.603 105.918,49.332 106.273,49.687 106.273,49.742 106.483,49.952 R169.1@106.578,49.952
  other v2: 67.94,45.755
eMMC.SDMMC2_CK: R103.1 U1.B25 U37.M6 | length 19.1
  Top Layer w0.09: U1.B25@68.375,47.325 68.402,47.352 68.402,48.575 ; 79.175,55.037 79.175,55.273 ; 79.175,55.537 79.175,55.773 ; 79.175,56.037 79.175,56.273
  Top Layer w0.11: 68.402,48.575 68.402,49.127 69.459,50.184 69.734,50.184 73.725,54.175 75.95,54.175 76.481,54.706 79.022,54.706 79.175,54.858 79.175,55.037 ; 79.175,55.273 79.175,55.405 ; 79.175,55.407 79.175,55.537 ; 79.175,55.773 79.175,55.905 ; 79.175,55.907 79.175,56.037 ; 79.175,56.273 79.175,56.372 79.095,56.452 79.095,56.87 79.281,57.056 v2(79.425,57.375) 79.705,57.655 U37.M6@79.925,57.655
  Bottom Layer w0.11: v2(79.425,57.375) 79.762,57.375 80.076,57.061 R103.1@80.171,57.061
eMMC.SDMMC2_CMD: R104.1 U1.D24 U37.M5 | length 20
  Top Layer w0.09: U1.D24@67.875,46.325 68.125,46.575 68.479,46.575 68.625,46.721 68.625,47.429 68.615,47.439 68.615,47.453 ; 79.675,55.037 79.675,55.273 ; 79.675,55.537 79.675,55.773 ; 79.675,56.037 79.675,56.273
  Top Layer w0.11: 68.616,47.451 68.615,47.453 68.615,47.933 68.625,47.943 68.625,48.699 69.588,49.662 69.816,49.662 74.034,53.881 76.181,53.881 76.699,54.399 79.162,54.399 79.675,54.911 79.675,55.037 ; 79.675,55.273 79.675,55.405 ; 79.675,55.407 79.675,55.537 ; 79.675,55.773 79.675,55.905 ; 79.675,55.907 79.675,56.037 ; 79.675,56.273 79.675,56.46 v2(79.45,56.685) U37.M5@79.92,57.155
  Bottom Layer w0.11: v2(79.45,56.685) 79.724,56.411 80.019,56.411 R104.1@80.175,56.255
eMMC.SDMMC2_D0: R101.1 U1.C24 U37.A3 | length 16
  Top Layer w0.09: U1.C24@67.875,46.825 67.88,46.83 67.88,47.467 67.985,47.572 67.985,48.335 67.902,48.418 67.902,48.575
  Top Layer w0.11: 67.902,48.575 67.902,49.85 71.229,53.177 71.487,53.435 71.597,53.435 71.743,53.289 71.852,53.289 71.962,53.399 71.962,53.508 71.778,53.692 71.778,53.801 71.888,53.911 71.998,53.911 72.181,53.727 72.291,53.727 72.4,53.837 72.4,53.947 72.217,54.13 72.217,54.24 72.326,54.349 72.436,54.349 72.62,54.166 72.729,54.166 72.839,54.275 72.839,54.385 72.655,54.569 72.655,54.678 72.765,54.788 72.874,54.788 73.058,54.604 73.168,54.604 73.277,54.714 73.277,54.823 73.131,54.969 73.131,55.079 73.279,55.227 v1(73.884,55.227) 73.884,55.909 74.13,56.155 U37.A3@74.425,56.155
  Bottom Layer w0.11: v1(73.884,55.227) 73.884,55.34 74.056,55.512 74.056,55.556 74.08,55.58 74.08,55.675 74.28,55.875 R101.1@74.375,55.875
eMMC.SDMMC2_D1: U1.B23 U37.A4 | length 18.8
  Top Layer w0.09: U1.B23@67.375,47.325 67.375,47.357 67.52,47.502 67.52,47.616 67.625,47.721 67.625,47.952 67.479,48.098 67.479,48.575
  Top Layer w0.11: 67.479,48.575 67.479,50.504 67.856,50.881 67.895,50.92 67.895,51.03 67.824,51.101 67.824,51.21 67.934,51.32 68.044,51.32 68.165,51.199 68.274,51.199 68.384,51.308 68.384,51.418 68.263,51.539 68.263,51.649 68.372,51.758 68.482,51.758 68.603,51.637 68.713,51.637 68.822,51.747 68.822,51.856 68.701,51.977 68.701,52.087 68.811,52.197 68.92,52.197 69.042,52.075 69.151,52.075 69.261,52.185 69.261,52.295 69.14,52.416 69.14,52.525 69.249,52.635 69.359,52.635 69.48,52.514 69.59,52.514 69.699,52.623 69.699,52.733 69.578,52.854 69.578,52.964 69.688,53.073 69.797,53.073 69.918,52.952 70.028,52.952 70.138,53.062 70.138,53.171 70.016,53.293 70.016,53.402 70.126,53.512 70.236,53.512 70.357,53.391 70.466,53.391 70.576,53.5 70.576,53.61 70.455,53.731 70.455,53.841 70.564,53.95 70.674,53.95 70.795,53.829 70.905,53.829 71.014,53.939 71.014,54.048 70.893,54.169 70.893,54.279 71.003,54.389 71.112,54.389 71.234,54.267 71.343,54.267 71.453,54.377 71.453,54.487 71.332,54.608 71.332,54.718 71.441,54.827 71.551,54.827 71.672,54.706 71.782,54.706 71.891,54.815 71.891,54.925 71.77,55.046 71.77,55.156 71.88,55.266 71.989,55.266 72.11,55.144 72.22,55.144 72.33,55.254 72.33,55.363 72.208,55.485 72.208,55.594 72.318,55.704 72.428,55.704 72.549,55.583 72.658,55.583 72.768,55.692 72.768,55.802 72.647,55.923 72.647,56.033 72.756,56.142 72.866,56.142 72.987,56.021 73.097,56.021 73.206,56.131 73.206,56.24 73.085,56.362 73.085,56.471 73.195,56.581 73.304,56.581 73.375,56.51 73.485,56.51 73.536,56.561 73.63,56.655 U37.A4@74.425,56.655
eMMC.SDMMC2_D2: U1.C23 U37.A5 | length 14.7
  Top Layer w0.09: 67.055,48.395 67.055,47.999 67.125,47.929 67.125,47.075 U1.C23@67.375,46.825
  Top Layer w0.11: 67.054,48.395 67.057,48.398 67.057,51.657 72.691,57.291 72.984,57.291 73.12,57.155 74.056,57.155 U37.A5@74.425,57.155
eMMC.SDMMC2_D3: U1.C25 U37.B2 | length 15.5
  Top Layer w0.09: 68.125,48.575 68.125,48.489 68.165,48.449 68.165,47.498 68.125,47.458 68.125,47.075 U1.C25@68.375,46.825 ; 74.675,54.705 74.675,55.273
  Top Layer w0.11: 68.125,48.575 68.125,49.525 69.225,50.625 69.647,50.625 69.723,50.702 69.762,50.741 69.762,50.85 69.621,50.991 69.621,51.101 69.731,51.211 69.84,51.211 70.004,51.046 70.114,51.046 70.224,51.156 70.224,51.266 70.059,51.43 70.059,51.539 70.169,51.649 70.279,51.649 70.443,51.485 70.552,51.485 70.662,51.594 70.662,51.704 70.498,51.868 70.498,51.978 70.607,52.087 70.717,52.087 70.881,51.923 70.991,51.923 71.1,52.033 71.1,52.142 70.936,52.307 70.936,52.416 71.046,52.526 71.155,52.526 71.32,52.362 71.429,52.362 71.539,52.471 71.539,52.581 71.375,52.745 71.375,52.855 71.484,52.964 71.594,52.964 71.735,52.823 71.845,52.823 71.887,52.865 73.582,54.56 74.596,54.56 74.675,54.639 74.675,54.705 ; 74.675,55.273 74.675,55.405 U37.B2@74.925,55.655
eMMC.SDMMC2_D4: U1.D22 U37.B3 | length 14.7
  Top Layer w0.09: U1.D22@66.902,46.352 U1.D22@66.875,46.325 67.229,46.325 67.625,46.721 67.625,47.075 67.7,47.15 67.7,47.541 67.805,47.647 67.805,48.17 67.7,48.275 ; 74.056,56.405 74.543,56.405
  Top Layer w0.11: 67.7,48.275 67.692,48.283 67.692,50.142 73.1,55.55 73.4,55.55 73.575,55.725 73.575,56.125 73.855,56.405 74.056,56.405 ; 74.543,56.405 74.675,56.405 U37.B3@74.925,56.155
eMMC.SDMMC2_D5: U1.A23 U37.B4 | length 17.3
  Top Layer w0.09: 67.267,48.575 67.267,48.055 67.349,47.973 67.349,47.851 U1.A23@67.375,47.825 ; 74.056,56.905 74.543,56.905
  Top Layer w0.11: 67.267,48.575 67.267,51.292 67.362,51.387 67.621,51.646 67.73,51.646 67.75,51.625 67.86,51.625 67.97,51.735 67.97,51.845 67.901,51.913 67.901,52.022 68.011,52.132 68.121,52.132 68.189,52.064 68.298,52.064 68.408,52.173 68.408,52.283 68.34,52.351 68.34,52.461 68.449,52.57 68.559,52.57 68.627,52.502 68.737,52.502 68.846,52.612 68.846,52.721 68.778,52.79 68.778,52.899 68.888,53.009 68.997,53.009 69.066,52.941 69.175,52.941 69.285,53.05 69.285,53.16 69.217,53.228 69.217,53.338 69.326,53.447 69.436,53.447 69.504,53.379 69.614,53.379 69.723,53.489 69.723,53.598 69.655,53.666 69.655,53.776 69.765,53.886 69.874,53.886 69.942,53.817 70.052,53.817 70.162,53.927 70.162,54.037 70.093,54.105 70.093,54.214 70.203,54.324 70.313,54.324 70.381,54.256 70.49,54.256 70.6,54.365 70.6,54.475 70.532,54.543 70.532,54.653 70.641,54.762 70.751,54.762 70.819,54.694 70.929,54.694 71.038,54.804 71.038,54.913 70.97,54.982 70.97,55.091 71.08,55.201 71.189,55.201 71.258,55.133 71.367,55.133 71.477,55.242 71.477,55.352 71.409,55.42 71.409,55.53 71.518,55.639 71.628,55.639 71.696,55.571 71.806,55.571 71.915,55.681 71.915,55.79 71.847,55.858 71.847,55.968 71.957,56.078 72.066,56.078 72.134,56.01 72.244,56.01 72.354,56.119 72.354,56.229 72.285,56.297 72.285,56.406 72.395,56.516 72.505,56.516 72.573,56.448 72.682,56.448 72.792,56.558 72.792,56.667 72.772,56.687 72.772,56.797 72.88,56.905 72.912,56.905 74.056,56.905 ; 74.543,56.905 74.675,56.905 U37.B4@74.925,56.655
eMMC.SDMMC2_D6: U1.A22 U37.B5 | length 14.8
  Top Layer w0.09: 66.847,48.356 66.847,48.176 66.875,48.148 U1.A22@66.875,47.825 ; 74.056,57.405 74.675,57.405
  Top Layer w0.096: 66.847,48.356 66.847,48.575
  Top Layer w0.11: 66.847,48.575 66.847,51.997 72.49,57.64 73.14,57.64 73.375,57.405 74.056,57.405 ; 74.675,57.405 U37.B5@74.925,57.155
eMMC.SDMMC2_D7: U1.B22 U37.B6 | length 16.1
  Top Layer w0.09: 66.625,48.575 66.625,47.575 U1.B22@66.875,47.325 ; 74.307,57.905 74.543,57.905
  Top Layer w0.11: 66.625,48.575 66.625,52.197 72.738,58.31 73.836,58.31 74.241,57.905 74.307,57.905 ; 74.543,57.905 74.675,57.905 U37.B6@74.925,57.655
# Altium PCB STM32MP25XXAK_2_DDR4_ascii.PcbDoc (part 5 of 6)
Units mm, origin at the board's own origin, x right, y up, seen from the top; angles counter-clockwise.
Board outline 120 x 79.6 mm, 4 copper layers (Top Layer, Signal Layer 1, Signal Layer 2, Bottom Layer), stack 1.614 mm thick; 243 components, 152 nets, 1304 pads, 784 vias.
Unrouted connection lines stored in the file: 6.

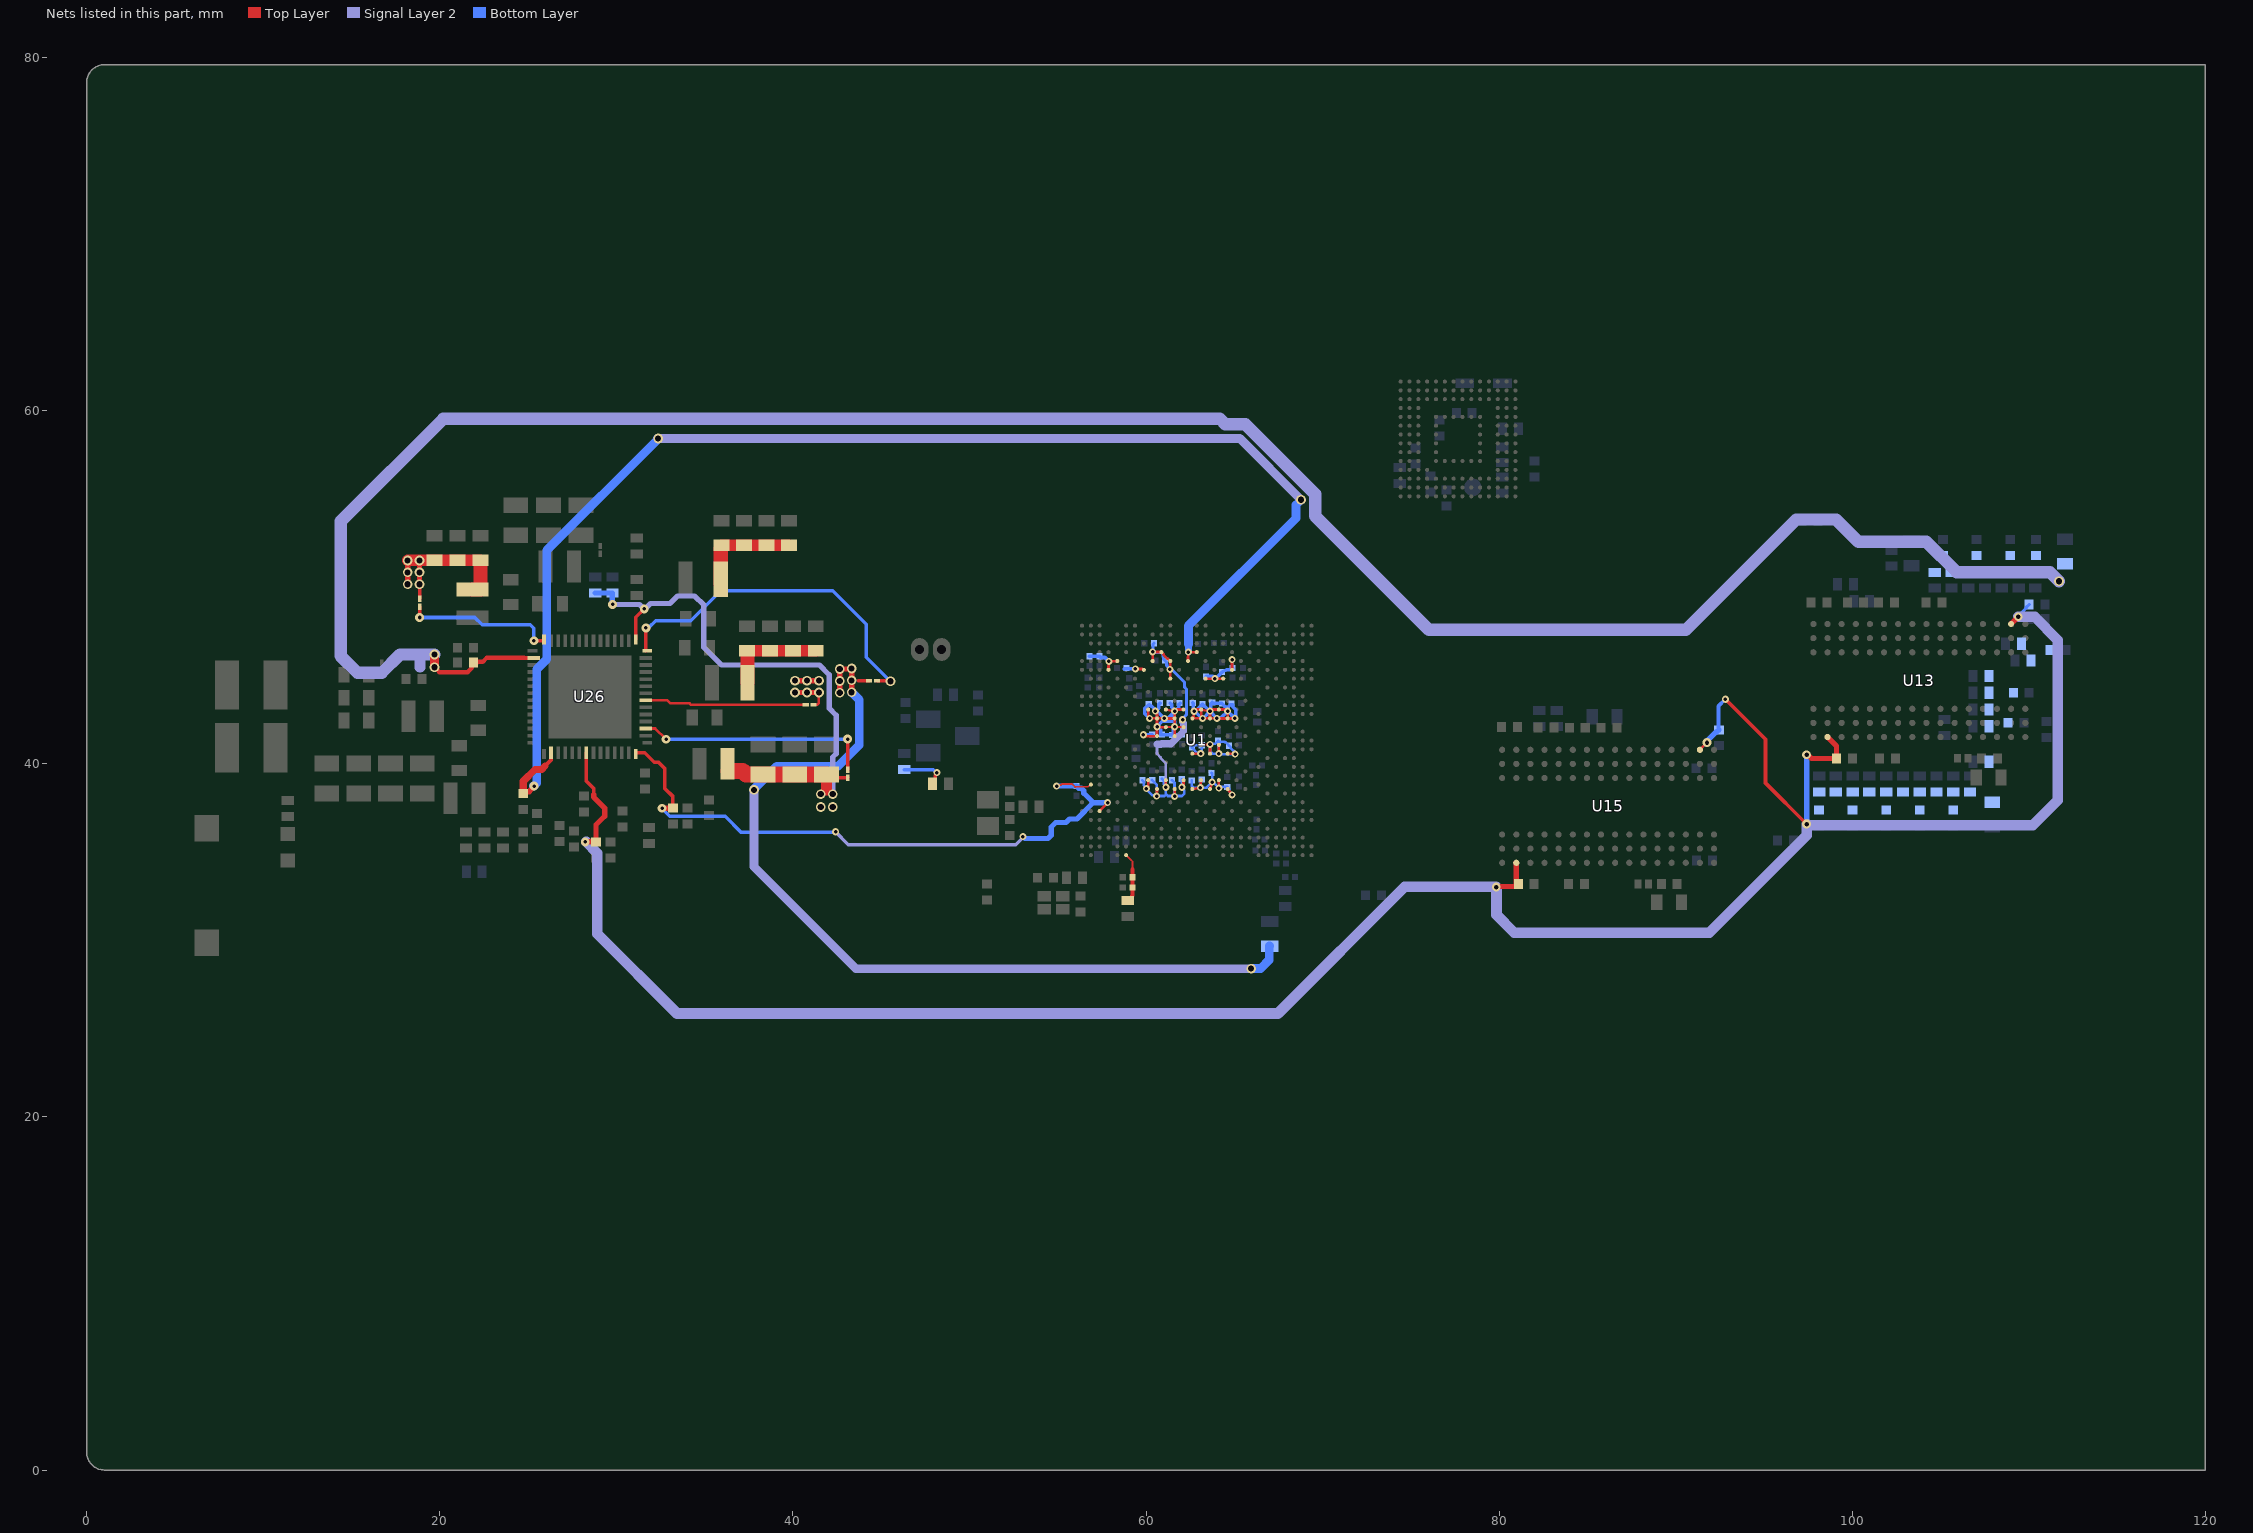
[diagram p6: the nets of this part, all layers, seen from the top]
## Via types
v1: diameter 0.55, hole 0.35, Top Layer to Bottom Layer, 256 vias
v2: diameter 0.4, hole 0.2, Top Layer to Bottom Layer, tented both sides, 235 vias
v3: diameter 0.5, hole 0.2, Top Layer to Bottom Layer, 146 vias
v4: diameter 0.5, hole 0.25, Top Layer to Bottom Layer, 143 vias
v5: diameter 0.5, hole 0.25, Top Layer to Bottom Layer, tented both sides, 4 vias

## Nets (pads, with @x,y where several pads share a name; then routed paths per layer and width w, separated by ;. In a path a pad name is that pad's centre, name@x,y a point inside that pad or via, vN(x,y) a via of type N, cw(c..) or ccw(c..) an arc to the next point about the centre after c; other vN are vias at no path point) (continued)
VDDA1V8_AON: C189.2 C234.2 U1.AB3 U1.W2 U26.14 | length 37.9
  Top Layer w0.09: 56.026,38.692 56.705,38.692 56.837,38.825 U1.W2@56.875,38.825 ; v2@57.825,37.775 v2(57.825,37.8)
  Top Layer w0.1: v2(54.932,38.744) 54.99,38.801 55.205,38.801 55.267,38.863 55.805,38.863 55.975,38.692 56.026,38.692
  Top Layer w0.15: U1.AB3@57.375,37.325 v2@57.825,37.775
  Top Layer w0.21: U26.14@31.1,40.63 31.61,40.63 32.148,40.092 32.387,40.092 32.745,39.734 32.745,38.602 33.2,38.147 C189.2@33.2,37.49
  Top Layer w0.3: v3(32.59,37.49) C189.2@33.2,37.49
  Signal Layer 2 w0.2: v2(42.415,36.154) 43.144,35.425 52.627,35.425 53.025,35.823 v2(53.025,35.875)
  Bottom Layer w0.2: v3@32.57,37.493 33.032,37.031 36.158,37.031 37.056,36.133 42.394,36.133 v2(42.415,36.154)
  Bottom Layer w0.3: v2(53.025,35.875) 53.052,35.875 53.152,35.775 53.829,35.775 53.836,35.769 54.451,35.769 54.627,35.944 54.627,36.412 54.891,36.675 55.461,36.675 55.662,36.877 56.088,36.877 57.012,37.8 ; v2(54.932,38.744) 54.936,38.748 C234.2@56.064,38.748 56.199,38.613 56.338,38.613 56.479,38.472 56.479,38.333 57.012,37.8 ; v2(57.825,37.8) 57.012,37.8
VDDCORE: C16.2 C22.2 C23.2 C24.2 C44.1 C45.2 C46.2 C47.1 C48.2 C49.2 C50.2 C51.2 C183.2 C192.2 C201.2 L2.2 LNK2.2 R11.1 U1.1C1 U1.1C3 U1.1C5 U1.1D2 U1.1D4 U1.1E3 U1.1E5 U1.1F2 U1.1F4 U1.E5 U1.F4 U1.F8 | length 78.4
  Top Layer w0.15: U1.F4@57.875,45.325 v2(57.9,45.8) U1.E5@58.375,45.825 ; v2(59.4,45.375) 59.803,45.375 59.853,45.325 U1.F8@59.875,45.325 ; v2(59.85,41.65) 59.904,41.65 59.981,41.573 U1.1F2@60.624,41.573 ; U1.1C1@60.125,43.075 60.125,42.724 60.206,42.643 v2@60.206,42.575 ; v2(60.21,42.575) U1.1D2@60.625,42.575 ; v2@60.545,42.99 60.545,42.922 60.625,42.842 U1.1D2@60.625,42.575 ; U1.1F2@60.625,41.65 v2(60.625,42.1) ; U1.1C3@61.125,43.075 v2(61.625,42.983) ; U1.1F4@61.625,41.575 v2(61.625,42.1) ; U1.1E5@62.125,42.075 v2(61.625,42.1) ; U1.1C5@62.125,43.075 61.771,43.075 61.679,42.983 v2(61.625,42.983) ; v2(60.625,42.1) U1.1D2@60.625,42.575 ; v2(60.625,42.1) 60.65,42.075 U1.1E3@61.125,42.075 v2(61.625,42.1) ; U1.1D2@60.625,42.575 61.017,42.572 61.622,42.572 U1.1D4@61.625,42.575 ; v2(61.625,42.1) U1.1D4@61.625,42.575 ; U1.1D4@61.625,42.575 v2@61.625,42.983
  Top Layer w0.2: C22.2@39.775,52.375 C22.2@39.823,52.423 ; 43.7,44.7 LNK2.2@44.316,44.7
  Top Layer w0.3: v1(42.656,44.024) v1(42.656,44.699) v1(42.656,45.374) 43.331,45.374 v1@43.331,44.024
  Top Layer w0.64: C183.2@35.95,52.375 C24.2@37.225,52.375 C23.2@38.5,52.375 C22.2@39.775,52.375
  Top Layer w0.8: L2.2@35.915,50.2 L2.2@35.915,50.45 C183.2@35.915,52.173
  Signal Layer 2 w0.5: v1(37.8,38.525) 37.798,38.523 37.798,34.168 43.576,28.39 v1@65.911,28.39 ; v1@65.911,28.391 65.947,28.391 v1(65.956,28.4)
  Bottom Layer w0.2: C192.2@56.8,46.1 C201.2@57.375,46.1 57.45,46.025 57.675,46.025 v2(57.9,45.8) ; C16.2@58.755,45.355 58.775,45.375 v2(59.4,45.375) ; v2(59.85,41.65) 60.346,41.65 C44.1@60.351,41.655 ; v2@60.206,42.575 59.942,42.839 59.942,43.153 60.059,43.27 60.098,43.27 60.173,43.345 60.198,43.32 60.235,43.32 60.285,43.27 60.328,43.27 60.507,43.091 60.507,43.028 60.545,42.99 v2@60.578,42.99 ; C51.2@60.814,43.438 60.788,43.438 60.725,43.375 60.725,43.137 v2@60.578,42.99 ; C46.2@60.84,41.657 C46.2@60.913,41.657 ; C46.2@60.915,41.655 C46.2@60.913,41.657 ; v2@61.135,42.572 61.017,42.572 61.017,42.591 60.719,42.89 60.699,42.89 60.599,42.99 v2@60.578,42.99 ; C49.2@61.377,43.437 61.452,43.362 61.452,43.201 61.625,43.028 v2(61.625,42.983) v2@61.616,42.961 ; C47.1@61.476,41.631 C47.1@61.502,41.657 ; C50.2@61.941,43.438 61.866,43.363 61.866,43.211 v2@61.616,42.961 ; C48.2@62.038,41.657 C47.1@61.502,41.657 ; C46.2@60.913,41.657 C47.1@61.502,41.657 ; C46.2@60.913,41.657 60.84,41.73 60.84,41.94 60.719,42.062 60.663,42.062 v2(60.625,42.1) 60.625,42.107 60.923,42.405 v2@61.06,42.405 ; v2@61.06,42.405 v2@61.227,42.572 ; v2@61.06,42.405 61.623,42.405 ; v2@61.227,42.572 v2@61.616,42.961 ; v2@61.227,42.572 61.455,42.572 ; 61.455,42.572 v2@61.616,42.961 ; 61.455,42.572 61.623,42.405 ; C47.1@61.502,41.657 61.551,41.706 61.551,41.972 61.625,42.046 v2(61.625,42.1) 61.623,42.102 61.623,42.405
  Bottom Layer w0.5: v1(37.8,38.525) 37.81,38.535 37.81,38.592 39.084,39.866 42.555,39.866 43.757,41.068 43.757,43.623 v1(43.326,44.054) ; v1(65.956,28.4) 66.485,28.4 66.983,28.898 66.983,29.658 R11.1@67,29.675
  other v1: 43.326,44.729 43.326,45.404
  other v2: 61.04,42.575 60.531,42.99
VDDCORE_FB: LNK2.1 U26.28 | length 20.6
  Top Layer w0.2: U26.28@31.67,46.4 v3(31.67,47.7) ; LNK2.1@44.766,44.7 v1@45.376,44.7
  Bottom Layer w0.2: v3@31.645,47.7 31.702,47.757 31.876,47.757 32.229,48.111 34.209,48.111 35.902,49.804 42.248,49.804 44.15,47.902 44.15,46.041 v1@45.508,44.683 ; v3@31.65,47.703 31.707,47.761 31.881,47.761 32.234,48.114
  other v1: 45.533,44.683
VDDCPU: C6.1 C7.2 C8.1 C10.2 C11.2 C26.2 C27.2 C28.2 C64.2 C68.2 C69.2 L3.2 LNK4.1 U1.1C7 U1.1C9 U1.1D6 U1.1D8 U1.1D10 U1.F18 U1.G15 U1.G17 | length 28
  Top Layer w0.15: v2@62.725,42.907 v2@62.725,42.975 ; v2@63.2,42.575 U1.1D6@62.625,42.575 62.625,42.597 62.696,42.668 62.696,42.956 v2(62.72,42.98) 62.788,42.98 62.883,43.075 U1.1C7@63.125,43.075 ; U1.G15@63.375,44.825 v2(63.9,44.825) U1.G17@64.375,44.825 ; U1.F18@64.875,45.325 v2(64.875,45.91) ; v2@65.017,42.572 64.628,42.572 U1.1D10@64.625,42.575 ; U1.1C7@63.125,43.075 63.125,42.728 63.21,42.643 v2(63.21,42.575) U1.1D8@63.625,42.575 ; U1.1C7@63.125,43.075 v2(63.625,42.983) ; U1.1D8@63.625,42.575 v2(63.625,42.983) ; U1.1D8@63.625,42.575 v2(64.017,42.572) 64.622,42.572 U1.1D10@64.625,42.575 ; v2(63.625,42.983) 63.693,42.983 63.784,43.075 U1.1C9@64.125,43.075 64.466,43.075 64.557,42.983 v2(64.625,42.983) U1.1D10@64.625,42.575
  Top Layer w0.2: LNK4.1@18.85,49.35 v1(18.85,50.173)
  Top Layer w0.3: v1(18.175,50.173) v1(18.175,50.848) v1(18.175,51.523) v1(18.85,51.523) v1(18.85,50.848) v1(18.85,50.173)
  Top Layer w0.64: v1(18.175,51.523) v1(18.175,51.523) C27.2@19.7,51.525 C28.2@21,51.525 C26.2@22.3,51.525
  Top Layer w0.8: L3.2@21.85,49.875 22.3,49.875 22.3,51.173
  Bottom Layer w0.15: v2(64.875,45.91) 64.895,45.89 C10.2@64.895,45.441
  Bottom Layer w0.2: C7.2@62.65,43.455 62.685,43.42 v2@62.685,43.015 ; C11.2@63.4,44.95 63.775,44.95 v2(63.9,44.825) 63.933,44.825 64.23,45.122 64.23,45.127 64.3,45.197 C69.2@64.305,45.197 ; v2(64.017,42.572) 64.055,42.61 64.252,42.61 v2(64.625,42.983) ; v2@64.017,42.583 v2@63.625,42.975 ; C69.2@64.305,45.202 64.579,45.324 64.778,45.324 64.886,45.432 64.91,45.423 C10.2@64.915,45.421 ; v2@64.587,43.138 C68.2@64.3,43.425 64.284,43.441 63.784,43.441 C8.1@63.75,43.475 63.675,43.4 63.675,43.088 63.625,43.038 v2(63.625,42.983) ; C64.2@64.902,43.35 64.775,43.35 64.658,43.233 64.658,43.016 v2(64.625,42.983) ; C64.2@64.908,43.345 64.908,43.242 65.078,43.072 65.078,42.61 v2(65.04,42.572) 65.036,42.572 65.011,42.597 v2(64.625,42.983) ; v2@63.625,42.975 v2(63.625,42.983) ; v2@63.625,42.975 63.625,42.963 63.237,42.575 63.169,42.575 62.764,42.98 v2(62.72,42.98) 62.758,43.018 62.843,43.018 C6.1@63.2,43.375 63.275,43.3 63.308,43.3 v2(63.625,42.983)
VDDCPU_FB: LNK4.2 U26.42 | length 8.6
  Top Layer w0.2: v3(18.85,48.29) LNK4.2@18.85,48.9 ; v3(25.325,46.975) U26.42@25.895,46.975
  Bottom Layer w0.2: v3(18.85,48.29) 21.979,48.29 22.394,47.875 25.123,47.875 25.325,47.673 v3(25.325,46.975)
VDDGPU: C1.2 C2.2 C3.2 C4.2 C5.2 C34.2 C35.2 C36.2 C37.2 C52.2 C58.2 C59.2 L4.2 LNK7.2 U1.1G7 U1.1G9 U1.1H6 U1.1H8 U1.1H10 U1.1L7 U1.1L9 U1.1M6 U1.1M8 U1.1M10 | length 24.7
  Top Layer w0.1: U1.1H6@62.625,40.575 U1.1H6@62.625,40.61
  Top Layer w0.125: v2(64.125,40.575) U1.1G9@64.125,41.075
  Top Layer w0.15: LNK7.2@41.175,43.35 41.182,43.358 41.385,43.358 41.473,43.445 v1(41.473,44.038) ; U1.1M6@62.625,38.575 v2(63.075,38.65) U1.1L7@63.125,39.075 ; U1.1H6@62.625,40.575 v2(63.1,40.575) ; U1.1G7@63.125,41.075 v2(63.625,41.1) U1.1H8@63.625,40.575 ; U1.1M8@63.625,38.575 v2(63.747,38.971) ; v2(64.125,38.629) U1.1L9@64.125,39.075 ; U1.1M10@64.625,38.575 v2(64.876,38.245)
  Top Layer w0.16: U1.1H10@64.625,40.575 v2(65.05,40.55)
  Top Layer w0.2: C35.2@41.55,46.393 C35.2@41.598,46.345
  Top Layer w0.3: v1(40.123,44.038) v1(40.798,44.038) v1(41.473,44.038) ; v1(40.123,44.713) v1(40.798,44.713) v1(41.473,44.713)
  Top Layer w0.64: C37.2@37.4,46.4 C36.2@38.7,46.4 C34.2@40,46.4 C35.2@41.3,46.4
  Top Layer w0.8: L4.2@37.425,44.6 37.425,46.073
  Bottom Layer w0.15: C4.2@62.592,39.053 62.592,38.738 62.68,38.65 v2(63.075,38.65) ; C5.2@63.154,39.122 63.092,39.06 63.092,38.667 v2(63.075,38.65) ; C59.2@63.714,39.486 63.747,39.453 v2(63.747,38.971) ; C1.2@64.091,41.314 64.163,41.243 64.444,41.243 64.458,41.229 64.507,41.229 64.605,41.131 64.605,41.129 C2.2@64.704,41.03 ; C2.2@64.705,41.029 64.805,40.929 64.805,40.883 65.002,40.686 65.002,40.598 v2(65.05,40.55) 64.15,40.55 v2(64.125,40.575) ; v2(64.876,38.245) 64.876,38.289 64.707,38.458 64.707,38.597 C58.2@64.607,38.697 64.193,38.697 v2(64.125,38.629) 63.783,38.971 v2(63.747,38.971) ; v2(63.075,38.65) 63.426,38.65 v2(63.747,38.971) ; C52.2@63.162,41.057 62.788,41.057 62.756,41.025 62.7,41.025 C3.2@62.6,40.925 62.902,40.623 63.052,40.623 v2(63.1,40.575) 63.162,40.637 C52.2@63.162,41.057 ; C52.2@63.162,41.057 63.184,41.079 63.603,41.079 v2(63.625,41.1) ; v2(63.625,41.1) 63.656,41.131 63.908,41.131 C1.2@64.083,41.306 64.083,40.962 64.125,40.919 v2(64.125,40.575) ; v2(63.625,41.1) 63.625,40.719 63.769,40.575 v2(64.125,40.575)
VDDGPU_FB: LNK7.1 U26.21 | length 9.3
  Top Layer w0.15: U26.21@31.55,43.6 32.883,43.6 33.06,43.423 34.14,43.423 34.213,43.35 LNK7.1@40.725,43.35
VDDIO: C12.1 C17.2 C19.2 C70.1 C71.2 C72.2 C74.2 C186.2 C187.2 C196.2 L6.2 LNK11.2 R27.2 R67.2 R260.2 R261.2 U1.1L1 U1.1L3 U1.1L5 U1.1M2 U1.1M4 U1.D10 U1.E9 U1.E11 U1.G11 U26.29 | length 59.1
  Top Layer w0.15: v2(60.025,38.6) 60.025,38.618 60.125,38.718 U1.1L1@60.125,39.075 ; U1.E9@60.375,45.825 U1.E9@60.397,45.825 ; U1.E9@60.375,45.825 v2(60.375,46.344) ; v2@60.448,46.335 U1.D10@60.865,46.335 ; v2(60.6,38.175) U1.1M2@60.625,38.575 ; U1.D10@60.875,46.325 60.875,46.322 61,46.197 61,46.17 61.22,45.95 61.247,45.95 61.372,45.825 U1.E11@61.375,45.825 61.375,45.448 61.362,45.435 61.375,45.423 U1.G11@61.375,44.825 ; v2(61.125,38.675) U1.1L3@61.125,39.075 ; U1.1M4@61.625,38.575 61.625,38.212 v2@61.663,38.175 ; v2@62.05,38.675 62.05,38.743 62.125,38.818 U1.1L5@62.125,39.075
  Top Layer w0.2: U26.29@31.1,47.045 31.1,48.298 v3(31.575,48.773) ; C186.2@41.9,39.4 42.085,39.215 LNK11.2@43.1,39.215 ; R27.2@47.905,38.872 48.06,39.027 48.06,39.347 48.158,39.446 v2(48.158,39.5)
  Top Layer w0.64: 41.9,38.525 C186.2@41.9,38.955
  Top Layer w0.9: L6.2@36.35,39.6 37.15,39.6 37.35,39.4 C187.2@38.3,39.4 C19.2@40.1,39.4 C186.2@41.9,39.4
  Signal Layer 2 w0.15: 60.633,41.112 60.619,41.098 60.619,40.581 60.827,40.373 60.827,40.328 61.125,40.03 v2(61.125,38.675)
  Signal Layer 2 w0.3: v3(29.784,49.027) 31.299,49.027 31.55,48.776 v3@31.575,48.776 ; v3(31.575,48.773) 31.629,48.773 31.94,49.084 33.043,49.084 33.473,49.513 34.431,49.513 34.955,48.989 34.955,46.601 35.956,45.6 41.499,45.6 42.051,45.048 42.051,43.156 42.451,42.756 42.451,40.573 42.252,40.375 v1(42.252,38.285)
  Signal Layer 2 w0.4: 60.633,41.112 60.859,41.112 60.885,41.138 61.426,41.138 62.125,41.837 62.125,42.307 62.072,42.36 v2(62.072,42.497)
  Bottom Layer w0.15: C70.1@59.781,39.075 59.881,38.975 59.881,38.787 60.025,38.643 60.025,38.55 60.352,38.223 60.552,38.223 v2(60.6,38.175) ; C71.2@60.34,39.085 60.6,38.825 v2(60.6,38.175) ; C72.2@60.905,39.148 61.005,39.048 61.005,38.863 61.125,38.743 v2(61.125,38.675) 61.125,38.285 ; C12.1@61.467,39.074 61.61,38.931 v2@61.61,38.175 ; v2(61.625,38.16) v2@61.61,38.175 ; C74.2@62.03,39.133 62.04,39.123 62.04,38.685 62.05,38.675 62.05,38.607 62.175,38.482 62.175,38.323 62.027,38.175 v2@61.61,38.175 ; v2(60.6,38.175) 61.037,38.175 61.125,38.263 61.125,38.285 ; 61.125,38.285 61.235,38.175 v2@61.61,38.175
  Bottom Layer w0.175: C17.2@60.452,46.829 60.389,46.765 v2@60.389,46.357 ; v2@60.485,46.38 60.411,46.38 v2@60.389,46.357 ; v2@61.35,45.366 61.35,45.39 61.175,45.565 61.175,45.66 61.163,45.672 61.163,45.762 61,45.925 61,46.01 60.968,46.042 60.968,46.188 60.85,46.305 60.413,46.305 v2(60.375,46.344) v2@60.389,46.357 ; v2@61.362,45.435 62.186,44.612 62.186,44.338 62.283,44.241 62.283,42.776 62.184,42.677 62.184,42.67 62.072,42.558 v2(62.072,42.497)
  Bottom Layer w0.2: R67.2@46.3,39.675 47.941,39.675 48.116,39.5 v2(48.158,39.5)
  Bottom Layer w0.3: R260.2@28.81,49.683 29.785,49.683 29.774,49.673 29.774,49.041 v3@29.764,49.031
  other v1: 41.577,37.56 42.252,37.56 41.577,38.285
  other v2: 62.03,38.675 61.35,45.35
VDDIO_FB: LNK11.1 U26.17 | length 13.4
  Top Layer w0.15: U26.17@31.67,42 32.2,42 32.803,41.397 v3(32.815,41.397)
  Top Layer w0.2: LNK11.1@43.1,39.665 v3(43.1,41.4)
  Bottom Layer w0.15: v3@43.097,41.397 v3(43.1,41.4)
  Bottom Layer w0.2: v3(32.815,41.397) v3@43.097,41.397
VDDIO_SDCARD: C195.2 C217.1 U1.D14 U1.E13 U26.2 | length 76.7
  Top Layer w0.15: U1.E13@62.375,45.825 v2(62.4,46.325) U1.D14@62.875,46.325
  Top Layer w0.21: 25.959,39.873 26.3,40.214 U26.2@26.3,40.63
  Top Layer w0.3: C217.1@24.725,38.38 24.77,38.425 25.059,38.425 25.335,38.701 v3(25.335,38.737)
  Top Layer w0.4: C217.1@24.725,38.32 24.725,38.38 24.725,39.015 25.399,39.69 25.775,39.69 25.959,39.873
  Signal Layer 2 w0.5: v1(32.365,58.43) 32.368,58.432 51.443,58.432 ; 51.445,58.435 51.443,58.432 ; v1(68.777,54.958) 65.303,58.432 51.443,58.432
  Bottom Layer w0.4: v2(62.4,46.325) C195.2@62.4,46.787
  Bottom Layer w0.5: v3@25.315,38.74 25.489,38.914 25.489,45.364 26.061,45.936 26.061,52.095 32.335,58.37 32.335,58.424 v1@32.345,58.433 ; C195.2@62.4,46.787 62.4,47.824 68.495,53.919 68.495,54.661 68.777,54.944 v1(68.777,54.958)
VPP_DDR: C66.2 C85.2 C91.1 C158.2 C203.2 U13.B1 U13.R9 U15.B1 U15.R9 U26.7 | length 140.4
  Top Layer w0.09: U15.B1@91.375,40.799 U15.B1@91.451,40.799
  Top Layer w0.15: U15.B1@91.381,40.8 v4@91.781,41.2
  Top Layer w0.2: v2(92.813,43.661) 92.824,43.661 95.092,41.393 95.092,38.915 v4(97.422,36.585)
  Top Layer w0.21: U26.7@28.3,40.63 28.3,39.025 28.715,38.61 28.715,38.253
  Top Layer w0.3: v3(28.24,35.58) C91.1@28.85,35.58 ; 28.715,38.253 28.715,38.118 29.335,37.498 29.335,37.035 28.85,36.55 C91.1@28.85,35.73 ; v4(79.841,33.017) 79.879,33.056 80.954,33.056 80.967,33.069 80.967,34.386 U15.R9@80.981,34.4 ; v4@97.421,40.534 97.461,40.534 97.696,40.299 C66.2@99.118,40.299 99.118,41.007 U13.R9@98.605,41.52 ; U13.B1@109.005,47.92 109.403,48.318 v4@109.403,48.32 ; v4@109.337,48.254 v4@109.403,48.32 ; v4(109.403,48.329) v4@109.403,48.32
  Signal Layer 2 w0.6: v3@28.285,35.58 28.919,34.946 28.919,30.374 33.436,25.857 67.474,25.857 74.652,33.036 79.823,33.036 79.854,33.004 79.854,31.455 80.867,30.443 91.912,30.443 97.422,35.953 v4@97.422,36.514 ; v4(97.422,36.585) v4@97.422,36.514 ; v4(109.403,48.329) 110.333,48.329 111.653,47.009 111.653,37.94 110.227,36.514 v4@97.422,36.514
  Bottom Layer w0.18: v4(109.403,48.329) 109.403,48.367 109.863,48.827 109.863,48.862 C158.2@110.028,49.027
  Bottom Layer w0.2: C203.2@92.428,41.929 92.428,43.276 v2(92.813,43.661)
  Bottom Layer w0.3: v4(91.778,41.204) 91.816,41.242 91.816,41.328 92.309,41.822 92.348,41.822 C203.2@92.453,41.927 ; v4(97.422,36.585) 97.433,36.596 v4@97.433,40.522
  other v4: 97.42,40.52
VREF+: C248.2 C250.2 R269.2 U1.AG6 | length 2.9
  Top Layer w0.09: U1.AG6@58.875,34.825 59.13,34.57
  Top Layer w0.1: 59.13,34.57 59.233,34.467 59.233,34.02
  Top Layer w0.25: R269.2@58.956,32.258 59.051,32.258 59.181,32.388 59.181,32.483 59.233,32.535 C248.2@59.233,33.002 C250.2@59.233,33.572 59.233,34.02
VTT_DDR: C40.2 C145.2 C146.2 C147.2 C148.2 C149.2 C170.2 C185.2 C198.2 C211.2 C212.2 C213.2 C214.2 C215.2 C216.2 R165.2 R166.2 R167.2 R168.2 R169.2 R170.2 R171.2 R175.2 R176.2 R177.2 R178.2 R180.2 R182.2 R183.2 R185.2 R186.2 R187.2 R188.2 R189.2 R190.2 R191.2 R192.2 R193.2 R194.2 U26.44 | length 130.9
  Top Layer w0.21: 24.775,46 U26.44@25.33,46
  Top Layer w0.25: v1(19.702,45.473) 19.975,45.2 21.575,45.2 21.82,45.445 21.82,45.635 21.935,45.75 C40.2@22.005,45.75 ; C40.2@22.01,45.635 22.165,45.79 22.44,45.79 22.65,46 24.775,46
  Top Layer w0.5: v1(19.702,45.473) v1@19.702,46.196
  Signal Layer 2 w0.6: 18.875,45.475 18.875,46.198
  Signal Layer 2 w0.7: v1(19.7,46.198) 18.875,46.198 17.744,46.198 16.709,45.163 15.337,45.163 14.383,46.117 14.383,53.733 20.199,59.549 64.181,59.549 64.498,59.232 65.634,59.232 69.577,55.289 69.577,54.036 76.026,47.587 90.575,47.587 96.829,53.842 99.094,53.842 100.359,52.576 104.204,52.576 105.928,50.852 111.204,50.852 v1(111.715,50.34)
pads on no net: U1.A3 U1.A6 U1.A7 U1.A10 U1.A11 U1.A14 U1.A15 U1.A18 U1.A19 U1.A26 U1.AA3 U1.AA5 U1.AA7 U1.AA9 U1.AA11 U1.AA13 U1.AA15 U1.AA17 U1.AA19 U1.AB1 U1.AB2 U1.AB8 U1.AB10 U1.AB12 U1.AB14 U1.AB16 U1.AB18 U1.AC2 U1.AC7 U1.AC9 U1.AC13 U1.AC15 U1.AC17 U1.AC19 U1.AC25 U1.AD4 U1.AD6 U1.AD8 U1.AD10 U1.AD12 U1.AD14 U1.AD16 U1.AD18 U1.AD20 U1.AD24 U1.AD25 U1.AE2 U1.AE3 U1.AE4 U1.AE5 U1.AE6 U1.AE7 U1.AE8 U1.AE9 U1.AE10 U1.AE11 U1.AE12 U1.AE13 U1.AE14 U1.AE15 U1.AE16 U1.AE17 U1.AE18 U1.AE19 U1.AE20 U1.AE24 U1.AE25 U1.AE26 U1.AF1 U1.AF3 U1.AF7 U1.AF9 U1.AF10 U1.AF11 U1.AF13 U1.AF14 U1.AF15 U1.AF17 U1.AF18 U1.AF19 U1.AF21 U1.AF22 U1.AF23 U1.AF25 U1.AF26 U1.AF27 U1.AG5 U1.AG9 U1.AG10 U1.AG13 U1.AG14 U1.AG17 U1.AG18 U1.AG21 U1.AG22 U1.AG25 U1.AG26 U1.B1 U1.B2 U1.B3 U1.B5 U1.B6 U1.B7 U1.B9 U1.B10 U1.B11 U1.B13 U1.B14 U1.B15 U1.B17 U1.B18 U1.B19 U1.B21 U1.B26 U1.B27 U1.C2 U1.C3 U1.C4 U1.C5 U1.C7 U1.C8 U1.C9 U1.C11 U1.C12 U1.C13 U1.C14 U1.C15 U1.C16 U1.C17 U1.C18 U1.C19 U1.C20 U1.C21 U1.C22 U1.C26 U1.C27 U1.D3 U1.D4 U1.D6 U1.D8 U1.D12 U1.D16 U1.D20 U1.D25 U1.E1 U1.E2 U1.E3 U1.F1 U1.F2 U1.F6 U1.F10 U1.G2 U1.G3 U1.G13 U1.G21 U1.G23 U1.H3 U1.H4 U1.J1 U1.J2 U1.J3 U1.J5 U1.K1 U1.K2 U1.K4 U1.K6 U1.L2 U1.L3 U1.L5 U1.L7 U1.L21 U1.M3 U1.M4 U1.M6 U1.N1 U1.N2 U1.N3 U1.N5 U1.N7 U1.P1 U1.P2 U1.P3 U1.P4 U1.P6 U1.R2 U1.R3 U1.R5 U1.T3 U1.T4 U1.U1 U1.U2 U1.U3 U1.U5 U1.U7 U1.V1 U1.V2 U1.V3 U1.V4 U1.W5 U1.Y3 U1.Y6 U1.Y24 U13.P9 U13.T7 U15.P9 U15.T7 U37.A1 U37.A2 U37.A7 U37.A8 U37.A9 U37.A10 U37.A11 U37.A12 U37.A13 U37.A14 U37.B1 U37.B7 U37.B8 U37.B9 U37.B10 U37.B11 U37.B12 U37.B13 U37.B14 U37.C1 U37.C3 U37.C5 U37.C7 U37.C8 U37.C9 U37.C10 U37.C11 U37.C12 U37.C13 U37.C14 U37.D1 U37.D2 U37.D3 U37.D4 U37.D12 U37.D13 U37.D14 U37.E1 U37.E2 U37.E3 U37.E5 U37.E8 U37.E9 U37.E10 U37.E12 U37.E13 U37.E14 U37.F1 U37.F2 U37.F3 U37.F10 U37.F12 U37.F13 U37.F14 U37.G1 U37.G2 U37.G3 U37.G10 U37.G12 U37.G13 U37.G14 U37.H1 U37.H2 U37.H3 U37.H12 U37.H13 U37.H14 U37.J1 U37.J2 U37.J3 U37.J12 U37.J13 U37.J14 U37.K1 U37.K2 U37.K3 U37.K6 U37.K7 U37.K10 U37.K12 U37.K13 U37.K14 U37.L1 U37.L2 U37.L3 U37.L12 U37.L13 U37.L14 U37.M1 U37.M2 U37.M3 U37.M7 U37.M8 U37.M9 U37.M10 U37.M11 U37.M12 U37.M13 U37.M14 U37.N1 U37.N3 U37.N6 U37.N7 U37.N8 U37.N9 U37.N10 U37.N11 U37.N12 U37.N13 U37.N14 U37.P1 U37.P2 U37.P7 U37.P8 U37.P9 U37.P10 U37.P11 U37.P12 U37.P13 U37.P14
copper on no net: | length 1378.9
  Top Layer w0.09: 39.873,56.227 53.275,42.825 56.875,42.825 ; 39.977,56.477 53.378,43.075 57.123,43.075 57.373,42.825 57.375,42.825 ; 40.175,57 53.85,43.325 56.375,43.325 ; 40.279,57.25 53.954,43.575 56.604,43.575 56.854,43.325 56.875,43.325 ; 40.575,57.875 54.625,43.825 56.375,43.825 ; 40.679,58.125 54.729,44.075 56.625,44.075 56.875,43.825 ; 40.8,58.825 55.301,44.324 57.374,44.324 ; 40.904,59.075 55.398,44.581 57.619,44.581 57.875,44.325 ; 40.925,59.8 55.9,44.825 56.875,44.825 ; 41.028,60.049 56.002,45.075 57.104,45.075 57.354,44.825 57.375,44.825 ; 41.372,60.697 53.744,48.325 56.941,48.325 57.105,48.161 57.105,47.949 57.125,47.929 57.125,47.575 57.373,47.327 57.375,47.327 ; 41.476,60.947 53.848,48.575 57.045,48.575 57.355,48.265 57.355,48.052 57.375,48.032 57.375,47.825 ; 41.622,61.627 54.147,49.101 57.05,49.101 57.625,48.526 57.625,46.575 57.875,46.325 ; 41.725,61.877 54.251,49.351 57.153,49.351 57.815,48.69 57.815,47.025 57.859,46.879 57.875,46.825 ; 41.962,62.567 54.586,49.943 57.188,49.943 58.005,49.126 58.005,47.232 58.375,46.862 58.375,46.825 ; 42.065,62.817 54.689,50.193 57.291,50.193 58.225,49.259 58.225,47.478 58.375,47.328 58.375,47.325 ; 47.601,58.348 55.092,50.857 57.854,50.857 58.65,50.061 58.65,48.127 58.625,48.102 58.625,47.721 58.86,47.486 58.86,47.34 58.875,47.325 ; 48.037,59.122 55.493,51.666 58.113,51.666 59.091,50.688 59.091,47.963 59.125,47.929 59.125,47.575 59.375,47.325 ; 48.141,59.372 55.597,51.916 58.216,51.916 59.341,50.792 59.341,48.066 59.375,48.032 59.375,47.825 ; 48.241,58.062 55.196,51.107 57.958,51.107 58.9,50.165 58.9,48.024 58.875,47.999 58.875,47.825 ; 51.21,57.126 53.846,54.489 55.788,52.548 58.415,52.548 59.531,51.432 59.531,48.2 59.695,48.036 59.695,47.752 59.625,47.682 59.625,47.174 59.625,47.073 59.377,46.825 59.375,46.825 ; 51.386,57.303 54.023,54.666 55.891,52.798 58.519,52.798 59.781,51.536 59.781,48.304 59.945,48.14 59.945,47.649 59.875,47.579 59.875,47.07 59.875,46.825 ; 53.528,34.458 53.958,34.888 54.709,34.888 55.078,35.258 55.53,35.258 55.847,35.575 56.979,35.575 57.125,35.721 57.125,35.736 57.188,35.798 57.348,35.798 57.375,35.825 ; 55.62,35.07 55.875,35.325 56.375,35.325 ; 55.625,36.655 56.67,36.655 56.84,36.825 56.875,36.825 ; 55.625,36.869 56.566,36.869 56.771,37.075 56.979,37.075 57.125,37.221 57.125,37.575 57.375,37.825 ; 55.625,37.075 56.479,37.075 56.702,37.298 56.848,37.298 56.875,37.325 ; 55.625,39.294 55.905,39.294 56.123,39.075 56.479,39.075 56.715,39.311 56.861,39.311 56.875,39.325 ; 55.625,39.494 55.959,39.494 56.128,39.325 56.375,39.325 ; v2@55.625,40.075 56.625,40.075 56.875,39.825 ; 55.625,40.42 55.648,40.42 55.793,40.275 56.68,40.275 56.73,40.325 57.375,40.325 ; 55.625,41.075 55.897,41.075 56.087,40.885 56.543,40.885 56.733,41.075 57.125,41.075 57.375,41.325 ; 55.625,41.494 56.038,41.494 56.182,41.35 56.35,41.35 56.375,41.325 ; 55.625,41.694 56.153,41.694 56.271,41.575 56.625,41.575 56.875,41.825 ; 55.625,41.894 56.207,41.894 56.251,41.85 56.35,41.85 56.375,41.825 ; 55.625,42.094 57.123,42.094 57.141,42.075 57.491,42.075 57.721,42.305 57.855,42.305 57.875,42.325 ; 55.625,42.294 57.252,42.294 57.257,42.298 57.348,42.298 57.375,42.325 ; 55.625,42.494 57.063,42.494 57.144,42.575 58.125,42.575 58.375,42.825 ; 55.92,36.07 55.925,36.075 56.625,36.075 56.875,35.825 ; 56.082,53.397 58.764,53.397 60.225,51.936 60.225,49.675 59.995,49.445 59.995,48.575 59.995,48.344 60.068,48.271 60.125,48.214 60.125,47.429 60.125,47.075 60.375,46.825 ; 56.114,38.255 57.267,38.255 57.337,38.325 57.375,38.325 ; 56.166,40.7 56.747,40.7 56.872,40.825 56.875,40.825 ; 56.183,38.89 56.188,38.895 56.553,38.895 56.733,39.075 57.125,39.075 57.374,39.324 ; 56.185,53.647 58.868,53.647 60.475,52.04 60.475,49.571 60.245,49.341 60.245,48.575 60.245,48.448 60.375,48.318 60.375,47.325 ; 56.195,41.075 56.479,41.075 56.702,41.298 56.848,41.298 56.875,41.325 ; 56.264,39.575 56.271,39.575 57.125,39.575 57.375,39.825 ; 56.279,54.255 59.174,54.255 60.9,52.529 60.9,49.45 60.53,49.08 60.53,48.575 60.53,48.529 60.625,48.434 60.625,47.575 60.875,47.325 ; 56.382,54.505 59.278,54.505 61.15,52.633 61.15,49.346 60.78,48.976 60.78,48.632 60.875,48.537 60.875,47.825 ; 56.655,40.505 57.055,40.505 57.375,40.825 ; 57.125,34.075 57.125,35.429 57.271,35.575 57.479,35.575 57.625,35.721 57.625,36.075 57.875,36.325 ; 57.325,34.075 57.325,34.605 57.375,34.655 57.375,35.325 ; 57.525,34.075 57.525,34.441 57.585,34.501 57.585,35.152 57.625,35.192 57.625,35.467 57.848,35.69 57.848,35.798 57.875,35.825 ; 57.76,34.344 57.765,34.349 57.765,35.078 57.805,35.118 57.805,35.363 58.24,35.798 58.348,35.798 58.375,35.825 ; v2@57.775,39.875 57.775,40.187 57.875,40.287 57.875,40.325 ; v2(57.79,38.85) 57.79,39.202 57.875,39.287 57.875,39.325 ; v2@57.9,41.825 58.375,41.825 ; 57.925,34.075 57.925,34.16 57.945,34.18 57.945,35.003 57.985,35.043 57.985,35.289 58.271,35.575 58.525,35.575 58.625,35.675 58.625,36.075 58.875,36.325 ; v2(58.349,38.315) 58.375,38.341 58.375,38.825 ; v2(58.375,37.35) 58.375,37.825 ; 58.375,43.825 58.388,43.813 58.862,43.813 v2@58.875,43.8 ; v2@58.391,42.3 58.416,42.325 58.875,42.325 ; v2@58.858,40.933 58.877,40.952 58.877,41.323 58.875,41.325 ; 58.875,35.825 59.125,35.575 59.125,35.104 ; 58.875,38.325 58.928,37.865 v2(58.939,37.77) ; v2@58.875,42.8 58.875,43.325 ; v2(59.45,46.325) 59.875,46.325 ; 59.625,35.629 59.625,36.075 59.875,36.325 ; 59.925,34.442 59.925,35.225 60.125,35.425 60.125,36.125 60.375,36.375 60.375,36.825 ; 60.125,34.59 60.125,35.075 60.375,35.325 ; 60.473,34.569 60.625,34.721 60.625,36.075 60.875,36.325 ; 60.679,34.372 60.875,34.568 60.875,34.825 ; 60.875,35.325 61.125,35.075 61.125,34.485 ; 61.375,34.075 61.375,35.325 ; 61.375,35.825 61.625,35.575 61.625,35.221 61.605,35.201 61.605,34.075 ; 61.375,46.825 61.765,47.215 61.765,47.607 61.826,47.668 61.826,48.429 61.972,48.575 ; 61.375,47.325 61.585,47.535 61.585,47.681 61.625,47.721 61.625,48.504 61.85,48.729 61.85,48.875 ; 61.88,46.83 61.895,46.845 61.895,47.09 61.945,47.14 61.945,47.532 62.065,47.652 62.065,48.407 62.233,48.575 ; 62.1,34.075 62.1,35.05 62.375,35.325 ; 62.362,34.075 62.362,34.812 62.375,34.825 ; 62.375,35.825 62.625,35.575 62.625,34.075 ; 62.375,46.825 62.125,47.075 62.125,47.458 62.265,47.598 62.265,48.345 62.45,48.53 62.45,48.575 ; 62.375,47.325 62.4,47.35 62.4,47.478 62.445,47.523 62.445,48.271 62.65,48.476 62.65,48.575 ; 62.85,48.575 62.85,48.421 62.625,48.196 62.625,47.075 62.875,46.825 ; 62.875,35.325 62.898,35.302 62.898,35.156 63.125,34.929 63.125,34.164 63.085,34.124 63.085,34.075 ; 62.875,35.825 63.125,35.575 63.125,35.221 63.305,35.041 63.305,34.075 ; 62.875,36.325 63.146,36.325 63.162,36.309 63.316,36.309 v2@63.375,36.25 ; v2@62.875,37.725 62.959,37.725 63.059,37.825 63.375,37.825 ; 62.875,47.325 63.125,47.575 63.125,48.17 63.251,48.297 63.251,48.575 ; 62.875,47.825 62.875,48.175 63.05,48.35 63.05,48.575 ; 63.375,35.318 63.375,35.293 63.515,35.153 63.515,34.075 ; 63.375,35.825 63.695,35.505 63.695,34.164 63.725,34.134 63.725,34.075 ; 63.375,46.825 63.825,47.275 ; 63.375,47.325 63.65,47.6 63.65,48.575 ; 63.875,35.825 63.875,35.334 63.945,35.264 63.945,34.647 63.949,34.643 63.949,34.075 ; 63.875,46.825 63.875,46.85 64.05,47.025 64.05,48.575 ; 64.154,34.075 64.154,34.693 64.125,34.721 64.125,35.075 64.375,35.325 ; 64.375,34.075 64.375,34.825 ; 64.375,35.825 64.625,35.575 64.625,34.635 ; 64.375,46.825 64.625,47.075 64.625,47.838 64.451,48.012 64.451,48.575 ; 64.851,48.575 64.851,48.203 65.125,47.929 65.125,47.075 64.875,46.825 ; 64.875,35.325 64.889,35.311 64.889,35.165 65.125,34.929 65.125,34.486 65.075,34.436 65.075,34.075 ; 64.875,35.825 65.125,35.575 65.125,35.183 65.305,35.003 65.305,34.411 65.29,34.396 65.29,34.085 65.28,34.075 65.275,34.07 65.275,34.04 ; 65.051,48.575 65.051,48.257 65.305,48.003 65.305,47.933 65.375,47.863 65.375,47.825 ; 65.375,35.325 65.375,35.29 65.485,35.18 65.485,34.08 65.48,34.075 ; 65.375,35.825 65.675,35.525 65.675,34.075 65.675,33.925 ; 65.375,46.825 65.625,47.075 65.625,47.229 65.695,47.299 65.695,47.537 65.805,47.647 65.805,48.166 65.63,48.342 65.63,48.575 ; 65.375,47.325 65.515,47.465 65.515,47.611 65.625,47.721 65.625,48.015 65.375,48.265 ; 65.875,34.075 65.875,35.825 ; 65.875,46.825 65.875,47.462 65.985,47.572 65.985,48.267 65.875,48.377 65.875,48.575 ; 66.125,48.396 66.165,48.356 66.165,47.446 66.115,47.396 66.115,47.085 66.375,46.825 ; 66.125,48.406 66.125,48.575 66.125,48.615 ; 66.375,47.325 66.375,52.65 ; 66.625,34.714 66.625,34.936 ; 68.375,46.325 68.492,46.325 68.742,46.575 68.979,46.575 69.119,46.715 69.119,46.922 69.273,47.077 69.58,47.077 70.016,47.513 70.091,47.513 70.555,47.976 ; 68.875,46.825 68.875,46.995 69.125,47.245 69.125,47.429 69.271,47.575 69.487,47.575 69.805,47.893 69.905,47.893 70.207,48.194 70.207,48.549 ; 68.889,47.339 68.889,47.485 69.125,47.721 69.125,48.118 69.582,48.575 ; 69.375,46.825 69.673,46.825 70.78,47.932 ; 69.375,47.325 69.398,47.348 69.529,47.348 69.884,47.703 70.012,47.703 70.51,48.2
  Top Layer w0.091: 65.475,33.994 65.475,34.001 65.48,34.006 65.48,34.075
  Top Layer w0.097: 63.65,48.575 63.65,48.681
  Top Layer w0.1: v2(43.9,37.12) 44.218,37.438 44.218,39.273 47.239,42.294 55.625,42.294 ; v2(44.4,37.12) 44.447,37.167 44.447,39.026 47.514,42.094 55.625,42.094 ; v2(44.8,38.125) 44.8,38.939 47.434,41.573 50.112,41.573 50.866,40.82 53.566,40.82 54.04,41.294 55.977,41.294 56.195,41.075 ; v2(45.3,38.125) 45.3,38.979 47.694,41.373 50.03,41.373 50.8,40.603 53.632,40.603 54.104,41.075 55.625,41.075 ; v2(45.8,38.125) 45.8,39.096 47.877,41.173 49.947,41.173 50.718,40.403 53.715,40.403 54.187,40.875 55.782,40.875 55.957,40.7 56.166,40.7 ; v2(45.825,36.825) 45.825,37.441 46.187,37.803 46.187,39.02 48.141,40.973 49.864,40.973 50.635,40.203 53.798,40.203 54.215,40.62 55.746,40.62 55.861,40.505 56.655,40.505 ; v2(46.325,36.825) 46.382,36.882 46.382,37.348 46.591,37.557 46.591,38.953 48.411,40.773 49.781,40.773 50.561,39.994 53.329,39.994 53.629,39.694 56.021,39.694 56.139,39.575 56.264,39.575 ; v2@46.875,36.833 46.875,38.78 48.669,40.573 49.698,40.573 50.478,39.794 53.247,39.794 53.546,39.494 55.625,39.494 ; v1(48.806,33.855) 50.209,35.258 53.188,35.258 53.573,35.643 54.396,35.643 54.727,35.974 54.727,36.37 55.012,36.655 55.625,36.655 ; v2(49.325,35.825) 49.692,35.458 53.105,35.458 53.501,35.854 54.306,35.854 54.527,36.074 54.527,36.453 54.943,36.869 55.625,36.869 ; v2(49.358,39.866) 49.83,39.394 50.019,39.394 50.021,39.392 50.476,39.392 50.478,39.394 53.081,39.394 53.381,39.094 55.843,39.094 56.047,38.89 56.183,38.89 ; v2(49.475,38.554) 49.913,38.992 50.642,38.992 50.644,38.994 52.847,38.994 53.391,38.45 54.448,38.45 54.704,38.194 55.16,38.194 55.402,38.435 55.695,38.435 55.875,38.255 56.114,38.255 ; v2(49.889,39.866) 50.162,39.594 53.164,39.594 53.464,39.294 55.625,39.294 ; v1(50.389,33.869) 50.482,33.869 51.471,34.858 53.36,34.858 53.765,35.263 54.553,35.263 54.939,35.648 55.355,35.648 55.777,36.07 55.92,36.07 ; v1(51.631,33.875) 52.214,34.458 53.528,34.458 ; v2(52.031,42.8) 52.337,42.494 55.625,42.494 ; v2(52.175,41.475) 52.525,41.125 52.849,41.125 53.417,41.694 55.625,41.694 ; v2(52.675,41.475) 53.094,41.894 55.625,41.894 ; 52.871,34.268 53.617,34.268 54.052,34.703 54.372,34.703 54.785,34.703 55.152,35.07 55.62,35.07 ; v2(53.389,41.17) 53.712,41.494 55.625,41.494 ; v2(53.45,36.225) 53.9,36.675 54.139,36.675 54.789,37.325 56.375,37.325 ; 54.014,29.76 55.661,29.76 56.837,30.936 56.837,31.895 57.325,32.383 57.325,34.075 ; v2(54.175,36.225) 54.175,36.384 54.866,37.075 55.625,37.075 ; v2(54.436,40.077) 54.779,40.42 55.625,40.42 ; v2(55.458,40.07) 55.463,40.075 v2@55.625,40.075 ; v2(56.956,32.51) 56.956,32.865 57.125,33.033 57.125,34.075 ; v2(57.271,30.195) 57.925,30.848 57.925,34.075 ; v2(57.271,30.982) 57.725,31.436 57.725,34.309 57.76,34.344 ; v2(57.275,31.8) 57.525,32.05 57.525,34.075 ; 57.375,43.825 57.77,43.825 v2(57.782,43.813) ; v2(57.79,40.85) 57.816,40.825 58.375,40.825 ; 57.875,41.325 57.899,41.325 57.999,41.425 v2@58.35,41.425 ; 57.875,43.325 v2(58.348,43.3) ; 58.325,30.282 58.325,33.533 58.325,34.354 58.375,34.404 58.375,34.825 ; v2(58.325,39.355) 58.375,39.405 58.375,39.825 ; v2(58.396,46.369) 58.875,46.325 ; v2(58.875,41.75) 58.932,41.807 59.039,41.807 59.056,41.825 59.375,41.825 ; 58.875,45.325 v2(58.875,45.9) ; 59.125,35.104 59.454,34.775 59.454,34.234 59.623,34.064 59.623,31.68 59.778,31.525 59.778,31.178 v2(59.781,31.175) ; v2@59.272,42.372 59.272,42.453 59.375,42.556 59.375,42.825 ; v2@59.3,39.367 59.316,39.465 59.375,39.825 ; v2(59.469,37.256) 59.802,37.313 59.875,37.325 ; 59.625,35.629 59.729,35.525 59.729,34.27 59.823,34.176 59.823,32.01 60.395,31.439 60.395,30.77 v2(60.375,30.75) ; 59.925,34.442 60.023,34.344 60.023,32.093 60.451,31.666 60.469,31.666 v2(60.96,31.175) ; 60.125,34.59 60.223,34.492 60.223,32.412 60.408,32.228 v2(60.408,32.204) ; v2@60.375,45.325 60.875,45.325 ; 60.473,34.569 60.423,34.52 60.423,32.746 v2(60.96,32.21) ; 60.679,34.372 60.623,34.316 60.623,33.097 v2(60.956,32.765) ; v2(60.973,33.601) 60.973,34.333 61.125,34.485 ; 61.225,54.759 62.25,53.734 62.25,48.594 62.233,48.577 62.233,48.575 ; 61.301,54.4 62.05,53.651 62.05,48.677 62.045,48.672 62.045,48.648 61.972,48.575 ; 61.325,53.425 61.637,53.113 61.637,48.792 61.375,48.53 61.375,47.825 ; v2(61.375,46.325) 61.875,46.325 ; 61.389,53.962 61.85,53.501 61.85,48.875 ; 61.65,54.617 62.45,53.817 62.45,48.575 ; 62.075,54.475 62.65,53.9 62.65,48.575 ; 62.375,44.825 v2(62.375,45.3) ; 62.649,54.184 62.85,53.983 62.85,48.575 ; 63.05,48.575 63.05,54.753 ; 63.25,55.155 63.25,48.576 63.251,48.575 ; 63.375,36.825 63.381,36.831 63.819,36.831 v2@63.875,36.775 ; v2@63.375,37.275 63.425,37.325 63.875,37.325 ; 63.375,47.825 63.375,48.159 63.451,48.235 63.451,48.575 63.451,48.597 63.45,48.598 63.45,55.572 ; 63.65,48.681 63.65,55.856 ; 63.825,47.275 63.85,47.3 63.85,48.575 63.85,56.423 ; 63.875,36.325 64.219,36.271 64.354,36.271 v2@64.375,36.25 ; v2(63.9,37.925) 63.94,37.885 64.055,37.885 64.375,37.825 ; 63.949,34.075 63.949,30.385 63.945,30.382 63.945,29.105 64.017,29.033 64.017,28.387 ; 64.05,48.575 64.05,56.294 ; 64.251,55.893 64.251,47.763 64.375,47.638 64.375,47.325 ; 64.375,34.075 64.375,29.626 64.904,29.097 64.904,28.387 ; 64.375,36.825 64.379,36.829 64.379,37.346 v2(64.375,37.35) ; 64.451,48.575 64.451,55.733 ; 64.625,34.635 64.625,29.701 65.331,28.995 65.331,28.141 65.5,27.973 65.5,26.55 ; 64.651,55.281 64.651,48.074 64.875,47.85 64.875,47.825 ; v2(64.8,37.75) 64.875,37.325 ; 64.851,48.575 64.851,54.9 65.325,55.374 ; 64.875,34.825 64.875,32.955 64.849,32.929 64.849,29.81 65.531,29.128 65.531,28.224 65.956,27.799 65.956,26.206 65.462,25.712 65.01,25.712 ; 64.875,36.325 v2(64.875,36.829) ; 65.051,48.575 65.051,54.817 65.525,55.291 ; 65.075,34.075 65.075,32.872 65.049,32.846 65.049,29.893 v2(65.956,28.986) ; 65.275,34.04 65.275,32.41 65.249,32.384 65.249,30.526 v2(65.5,30.275) ; v2@65.375,36.275 65.375,36.825 ; 65.375,37.825 65.55,37.65 65.55,37.174 65.74,36.985 65.74,36.76 v2@65.775,36.725 ; 65.475,33.994 65.475,32.327 65.449,32.301 65.449,30.993 66.003,30.439 v2(66.003,29.72) ; 65.675,33.925 65.675,32.244 65.649,32.218 65.649,31.294 v2(65.999,30.944) ; 65.875,34.075 65.875,32.555 65.999,32.431 65.999,32.073 ; 66.375,34.825 66.375,32.814 66.854,32.335 ; 66.375,35.325 66.12,35.07 66.12,34.719 66.155,34.684 66.155,33.97 66.155,32.723 66.634,32.244 ; 66.625,34.714 66.625,33.208 67.52,32.313 67.52,30.227 68.321,29.425 70.516,29.425 ; 66.625,34.936 66.625,35.075 66.875,35.325 ; 66.875,34.825 66.875,34.075 66.875,33.269 67.74,32.404 67.74,30.318 68.412,29.645 70.607,29.645
  Top Layer w0.11: 56.657,28.898 56.73,28.825 60.735,28.825 62.1,30.19 62.1,34.075 ; 56.938,29.15 60.654,29.15 61.85,30.346 61.85,34.075 61.85,35.15 61.875,35.175 ; 58.066,29.495 60.595,29.495 61.605,30.505 61.605,34.075 ; v2(60.389,30.112) 60.422,30.112 61.375,31.065 61.375,34.075 ; 60.776,28.495 62.362,30.081 62.362,34.075 ; 61.545,28.065 61.545,28.845 62.625,29.925 62.625,34.075 ; 61.56,26.465 62.145,26.465 62.957,27.277 62.957,28.826 63.085,28.954 63.085,34.075 ; 61.56,27.24 62.115,27.24 62.747,27.872 62.747,28.913 62.875,29.041 62.875,34.075 62.875,34.825 ; 61.875,35.178 61.875,35.793 ; v2@62.375,36.25 62.375,36.825 ; v2@62.375,37.275 62.375,37.825 ; v2@62.875,36.75 62.875,37.325 ; 63.167,26.426 63.167,28.739 63.305,28.877 63.305,34.075 ; 63.377,25.821 63.377,28.652 63.515,28.79 63.515,34.075 ; 63.587,28.565 63.725,28.703 63.725,34.075 ; 63.797,27.389 64.457,28.048 64.457,29.066 64.154,29.369 64.154,34.075 ; 65.375,48.265 65.375,54.493 67.076,56.194 68.179,57.298 68.8,57.918 ; 65.63,48.575 65.63,54.198 69.225,57.793 ; 65.875,48.575 65.875,53.79 69.841,57.756 ; 66.125,48.615 66.125,53.21 67.275,54.36 67.275,54.59 68.803,56.118 69.018,56.118 70.375,57.475 70.375,58.349 ; 66.375,52.65 67.75,54.025 67.75,54.538 68.909,55.697 69.051,55.697 70.976,57.622 70.976,58.076 ; 68.875,47.825 68.884,47.834 68.884,48.387 69.706,49.209 69.909,49.209 74.284,53.584 ; 69.582,48.575 69.831,48.824 70.025,48.824 74.476,53.275 ; 70.207,48.549 74.617,52.959 ; 70.78,47.932 75.008,52.16
  Top Layer w0.15: v2(59.989,37.734) v2(59.989,37.734) 60.264,37.736 60.353,37.825 60.375,37.825 ; v2(60.95,37.8) 60.971,37.779 61.307,37.779 61.353,37.825 61.375,37.825
  Bottom Layer w0.09: 57.296,40 57.517,40 57.582,39.934 57.731,39.934 v2(57.79,39.875)
  Bottom Layer w0.1: v2(49.475,38.554) v2@49.475,38.632 ; v2@52.028,42.803 v2(52.031,42.8) ; 56.233,43.813 v2(57.782,43.813) ; 56.314,43.463 57.927,43.463 58.264,43.8 v2(58.85,43.8) ; 56.899,40.849 57.286,40.849 57.287,40.85 v2(57.79,40.85) ; 57.509,43.191 57.742,43.191 57.821,43.27 58.003,43.27 58.033,43.3 v2(58.348,43.3) ; 57.635,42.575 57.64,42.57 58.111,42.57 58.241,42.7 58.25,42.7 58.29,42.74 v2(58.875,42.74) ; 57.642,42.18 57.923,42.18 58.177,41.926 58.553,41.926 58.999,42.371 59.286,42.371 v2(59.29,42.375) ; 57.792,42.385 57.794,42.384 57.991,42.384 58.183,42.384 58.209,42.357 58.334,42.357 v2@58.391,42.3 ; 58.287,40.933 v2@58.858,40.933 ; 59.375,46.875 59.089,46.589 59.089,46.192 59.431,45.85 59.478,45.85 60.003,45.325 v2@60.375,45.325 ; v2(59.45,46.325) 59.441,46.334 59.441,46.616 59.55,46.725 59.575,46.75 ; v2(61.375,46.325) 61.375,48.53 66.362,53.518 ; 62.787,24.149 62.787,33.049 63.813,34.075 64.058,34.32 64.058,35.64 63.714,35.984 63.714,36.413 63.529,36.598 63.529,36.999 64.28,37.75 v2(64.8,37.75) ; 62.987,24.066 62.987,32.683 62.987,32.966 64.096,34.075 64.248,34.227 64.248,35.719 63.973,35.994 63.973,36.342 64.375,36.744 v2(64.375,37.35) ; 63.187,23.983 63.187,32.883 64.379,34.075 64.438,34.135 64.438,35.85 64.438,35.858 64.338,35.959 64.338,36.213 v2@64.375,36.25 ; 63.387,23.901 63.387,32.8 64.579,33.992 64.579,33.995 64.658,34.075 64.658,35.887 64.798,36.026 64.798,36.474 64.866,36.543 64.866,36.82 v2(64.875,36.829) ; 63.587,23.818 63.587,32.717 64.858,33.989 64.858,34.075 64.858,35.78 64.988,35.909 64.988,36.395 65.38,36.787 65.414,36.821 65.608,36.821 65.704,36.725 v2@65.775,36.725
  Bottom Layer w0.11: 57.752,31.425 60.402,34.075 60.865,34.538 60.865,35.768 v2@61.335,36.239 ; 57.777,30.55 60.458,33.23 60.458,33.588 61.525,34.655 61.525,35.349 62.375,36.199 v2(62.375,36.24) ; 57.977,32.227 60.475,34.725 60.475,35.978 61.249,36.751 v2@61.872,36.751 ; 58.127,33.021 59.18,34.075 59.653,34.548 59.653,36.273 60.654,37.274 61.955,37.274 v2@62.374,37.274 ; 61.525,31.919 61.525,33.498 62.528,34.501 62.528,35.901 62.875,36.248 v2@62.875,36.75 ; 61.981,31.469 61.981,33.039 63.375,34.433 v2@63.375,36.25 ; v2(62.375,45.3) 62.375,45.848 62.045,46.178 61.906,46.317 61.906,48.34 67.341,53.775
  other v1: 68.584,30.569
  other v2: 61.3,36.24 63.375,36.24 64.375,36.24 65.375,36.24 61.875,36.74 62.875,36.74 65.78,36.73 63.9,36.775 46.875,36.825 62.375,37.24 63.385,37.265 62.875,37.76 59.345,39.355 58.858,40.91 58.28,41.421 57.79,41.825 58.4,42.275 60.375,45.35 66.28,46.42

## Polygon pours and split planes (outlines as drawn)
GND on Signal Layer 2 "GND_L03_P054" (solid, remove dead copper, pour order 54): -0.734,79.601 120,79.601 120,44.244 120,0.001 -0.734,0.001
VDD_DDR on Signal Layer 2 "VDD_DDR" (solid, remove dead copper, pour order 48): 17.719,49.75 17.749,49.781 21.619,49.781 21.85,49.55 21.845,49.545 21.845,46.79 21.527,46.471 17.719,46.471 16.716,45.468 15.418,45.468 14.746,46.14 14.746,53.378 19.353,57.985 64.94,57.985 75.791,47.134 90.762,47.134 97.006,53.378 98.898,53.378 100.106,52.197 103.96,52.197 105.749,50.37 108.897,50.358 110.565,50.358 110.727,50.196 110.727,48.528 111.867,47.388 111.867,38.656 110.075,36.84 97.741,36.84 91.749,30.848 80.262,30.848 80.241,30.848 78.457,32.632 72.212,32.632 69.951,34.905 68.067,34.892 66.119,36.84 65.275,36.84 65.275,42.724 65.395,42.844 65.395,44.606 66.079,45.291 66.079,46.314 66.079,48.276 63.82,50.536 62.26,52.095 18.039,52.095 17.719,51.775
VDDCPU on Signal Layer 2 "VDDCPU" (solid, remove dead copper, pour order 47): 65.318,42.75 63.344,40.776 63.333,40.775 61.131,40.775 61.131,44.645 61.131,45.532 60.118,46.545 34.955,46.545 34.955,48.62 35.005,48.67 34.675,49 28.643,49 28.555,48.912 27.616,49.85 17.819,49.85 17.719,49.75 17.719,51.775 19.343,53.4 28.217,53.4 29.103,52.513 29.103,52.5 61.855,52.5 66.016,48.339 66.016,44.697 65.318,43.998
1V8 on Signal Layer 2 "1V8_L03_P052" (solid, pour order 52): 29.175,64.6 29.175,61.472 70.193,61.472 70.252,51.21 84.26,51.21 86.225,53.175 86.225,64.6
5V_STLK on Signal Layer 2 "5V_STLK_L03_P051" (solid, pour order 51): 11.875,50.635 37.435,50.635 37.475,50.595 37.475,31.99 14.15,31.99 11.911,34.229
3V3 on Signal Layer 2 "3V3_L4" (solid, remove dead copper, pour order 50): 26.5,29.394 26.439,29.394 6.483,29.394 4.211,29.394 4.211,35.822 4.211,52.011 12.936,52.011 12.936,41.55 13.947,40.539 26.5,40.539
VDDGPU on Signal Layer 2 "VDDGPU" (solid, remove dead copper, pour order 45): 65.482,41.332 65.482,37.836 67.041,36.277 67.041,32.841 64.416,30.216 41.23,30.216 37.77,33.607 37.77,38.917 35.099,41.523 35.099,43.759 36.63,45.29 42.13,45.29 42.13,40.863 41.049,39.782 41.049,37.54 42.874,35.715 57.874,35.715 60.107,37.923 61.767,37.923 61.941,38.097 61.941,38.49 61.941,41.332
VDDCORE on Signal Layer 2 "VDDCORE" (solid, remove dead copper, pour order 46): 61.618,43.605 61.618,45.055 59.673,47 42.245,47 42.245,41.019 62.343,41.019 62.343,42.83
VDDIO on Signal Layer 2 "VDDIO" (solid, remove dead copper, pour order 49): 62.352,38.39 61.735,37.772 60.085,37.772 57.878,35.564 42.878,35.564 41.053,37.389 41.053,39.646 42.445,41.038 61.524,41.038 62.352,40.21
GND on Top Layer "GND_L01_P053" (solid, remove dead copper, pour order 53): 0,79.797 120,79.797 120,0.197 0,0.197
5V_STLK on Top Layer "5V_VIN" (solid, pour order 17): 22.51,43.62 23.167,43.62 23.35,43.803 23.35,43.463 22.867,42.98 22.51,42.98
VDDCPU on Top Layer "VDDCPU_TOP" (solid, pour order 18): 17.812,51.845 17.812,49.998 18.335,49.475 22.75,49.475 22.745,49.48 22.745,51.845
VDDCORE on Top Layer "VDDCORE_TOP" (solid, pour order 19): 41.007,52.695 43.889,49.813 43.889,43.586 43.894,43.581 42.44,43.581 41.895,44.126 41.895,48.827 41.522,49.2 39.875,49.2 35.515,49.2 35.505,52.695
VDDGPU on Top Layer "VDDGPU_TOP" (solid, pour order 20): 41.603,43.6 41.745,43.742 41.745,46.72 37.025,46.72 37.025,43.6
VDDIO on Top Layer "VDDIO" (solid, pour order 22): 30.995,46.77 30.995,48.568 31.53,49.103 31.712,49.103 32.15,48.664 32.15,48.123 31.45,47.423 31.45,46.77
3V3 on Top Layer "3V3" (solid, pour order 23): 12.887,36.548 13.062,36.373 19.41,36.373 20.712,37.675 20.712,38.523 13.088,38.523 12.887,38.323
NetL6_1 on Top Layer "NetL13_1" (solid, pour order 25): 33.375,41.863 33.838,41.4 35.1,41.4 35.1,39.1 35.098,39.098 33.801,39.098 33.801,40.722 33.375,41.148
GND on Bottom Layer "GND_L04_P056" (solid, remove dead copper, pour order 56): 0.261,79.382 120,79.382 120,-0.218 0.261,-0.218
VTT_DDR on Bottom Layer "VTT_DDR_L04_P055" (solid, remove dead copper, pour order 55): 109.733,41.843 109.998,41.578 109.998,36.927 97.737,36.927 97.737,38.864 107.278,38.864 107.278,45.398 109.703,45.398 109.703,46.338 109.16,46.338 109.171,47.173 110.437,47.173 111.378,47.927 111.378,49.327 110.953,49.752 110.953,50.373 104.403,50.373 104.378,50.348 104.328,50.398 104.328,52.073 112.628,52.073 112.628,49.698 112.628,47.273 112.216,46.862 111.82,46.862 111.653,46.695 111.653,45.827 110.348,44.523 109.703,44.523 109.578,44.398 109.578,43.623 109.703,43.498 109.703,42.803 109.278,42.803 109.278,41.843
GND on Signal Layer 1 "GND_L02_P000" (solid, remove dead copper, pour order 0): 0,79.6 120,79.6 120,0 0,0

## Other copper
Top Layer:
  rectangle net VDD_DDR: 15.655,41.8 18.625,43.6

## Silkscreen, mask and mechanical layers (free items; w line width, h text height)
Top Overlay:
  text "J" at 27.263,70.56 h15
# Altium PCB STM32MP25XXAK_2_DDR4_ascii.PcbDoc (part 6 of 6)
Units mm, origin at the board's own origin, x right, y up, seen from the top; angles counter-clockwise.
Board outline 120 x 79.6 mm, 4 copper layers (Top Layer, Signal Layer 1, Signal Layer 2, Bottom Layer), stack 1.614 mm thick; 243 components, 152 nets, 1304 pads, 784 vias.
Unrouted connection lines stored in the file: 6.

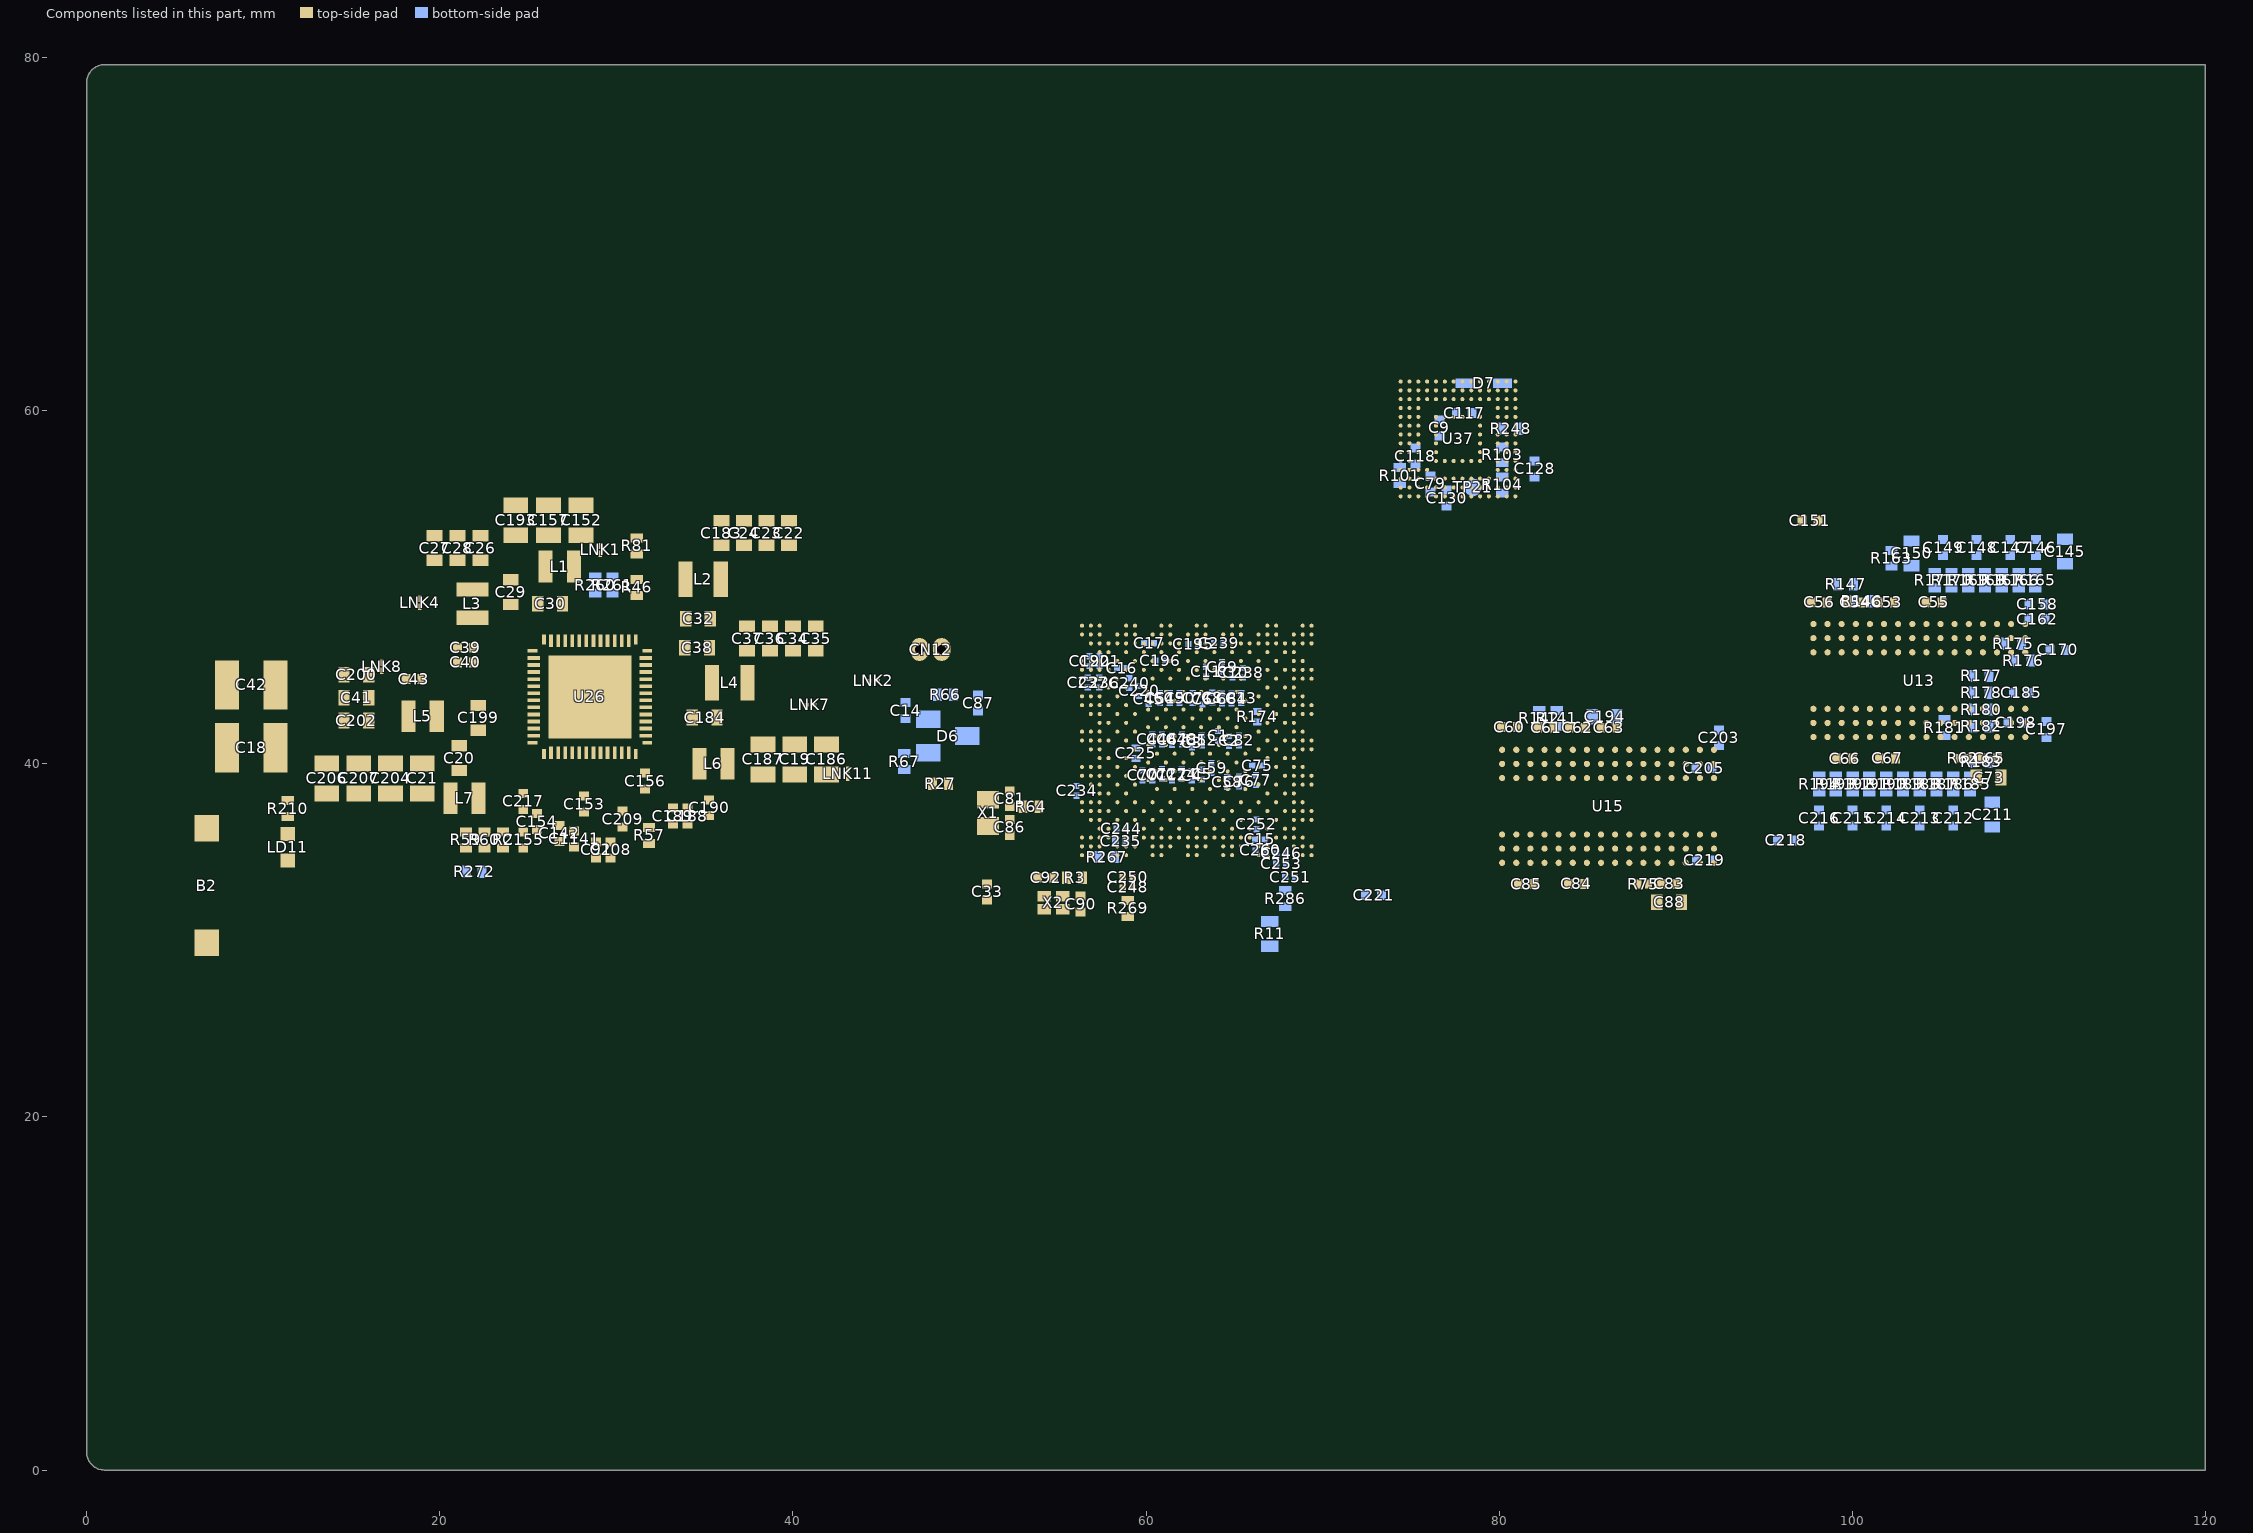
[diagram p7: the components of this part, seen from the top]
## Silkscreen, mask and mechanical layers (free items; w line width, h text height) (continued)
Drill Drawing:
  drawing of 194 lines, arcs and shapes, not listed
  text "PCB SPECIFICATIONS :" at -27.02,127.275 h3
  text "A.   MATERIAL :" at -27.02,123.275 h3
  text "FR-4" at 11.48,123.275 h3
  text "TG-170" at 27.98,123.275 h3
  text "X  TG-150" at 46.23,123.275 h3
  text "TG-140" at 62.23,123.275 h3
  text "B.   MATERIAL FAMILY :" at -27.02,120.275 h3
  text "N/A" at 11.48,120.275 h3
  text "C.   SOLDERMASK COLOR :" at -27.02,117.275 h3
  text "GREEN" at 11.48,117.275 h3
  text "X  BLUE" at 27.98,117.275 h3
  text "RED" at 46.23,117.275 h3
  text "BLACK" at 62.23,117.275 h3
  text "D.   SILKSCREEN COLOR :" at -27.02,114.275 h3
  text "X  WHITE" at 11.48,114.275 h3
  text "YELLOW" at 27.98,114.275 h3
  text "BLACK" at 46.23,114.275 h3
  text "PCB : TYPE 4" at 187.138,113.471 h3
  text "Layer" at 122.2,111.475 h2
  text "Name" at 130.564,111.475 h2
  text "Material" at 146.732,111.475 h2
  text "Thickness" at 161.266,111.475 h2
  text "Constant" at 173.202,111.475 h2
  text "E.   SURFACE FINISH :" at -27.02,111.275 h3
  text "X  ENIG" at 11.48,111.275 h3
  text "IMMERSION SILVER" at 27.98,111.275 h3
  text "IMMERSION TIN" at 62.23,111.275 h3
  text "HASL" at 11.48,108.275 h3
  text "HASL (PB-FREE)" at 27.98,108.275 h3
  text "GOLDEN FINGER" at 62.23,108.275 h3
  text "ASPECT-RATIO, AXE Z :" at 187.138,107.971 h3
  text "Top Overlay" at 130.564,107.475 h2
  text "F.   IMPEDANCE CONTROL :" at -27.02,105.275 h3
  text "NO" at 11.48,105.275 h3
  text "X  YES" at 27.98,105.275 h3
  text "Top Solder" at 130.564,103.475 h2
  text "Solder Resist" at 146.732,103.475 h2
  text "0.025mm" at 161.266,103.475 h2
  text "3.5" at 173.202,103.475 h2
  text "G.   THROUGH VIA :" at -27.02,102.275 h3
  text "PLUG THE VIAS WHICH ARE COVERED WITH SOLDERMASK ONE OR TWO SIDE." at 11.48,102.275 h3
  text "6 :1  to  8 :1 / LEVEL \"B\"" at 187.157,101.224 h3
  text "1" at 122.2,99.475 h2
  text "Top Layer" at 130.564,99.475 h2
  text "0.037mm" at 161.266,99.475 h2
  text "PLUG MATERIAL :" at 11.48,99.275 h3
  text "X  SOLDERMASK" at 36.98,99.275 h3
  text "NON-CONDUCTIVE EPOXY." at 62.23,99.275 h3
  text "H.   STACK-UP :" at -27.02,96.275 h3
  text "SEE LAYER STACK-UP SEQUENCE FOR OVERALL THICKNESS." at 11.48,96.275 h3
  text "Dielectric 1" at 130.564,95.475 h2
  text "0.070mm" at 161.266,95.475 h2
  text "3.8" at 173.202,95.475 h2
  text "2" at 122.198,91.475 h2
  text "Signal Layer 1" at 130.564,91.475 h2
  text "0.035mm" at 161.266,91.475 h2
  text "MINIMUN PARAMETERS" at 187.25,89.695 h3
  text "Dielectric 2" at 130.564,87.475 h2
  text "1.330mm" at 161.266,87.475 h2
  text "4.3" at 173.202,87.475 h2
  text "DEFAULT" at 187.25,84.195 h3
  text "3" at 122.2,83.475 h2
  text "Signal Layer 2" at 130.564,83.475 h2
  text "0.035mm" at 161.266,83.475 h2
  text "Dielectric 3" at 130.564,79.475 h2
  text "0.070mm" at 161.266,79.475 h2
  text "3.8" at 173.202,79.475 h2
  text "TRACKS : 0.100mm           / GAPS : 0.100mm" at 187.25,78.445 h3
  text "4" at 122.2,75.475 h2
  text "Bottom Layer" at 130.564,75.475 h2
  text "0.037mm" at 161.266,75.475 h2
  text "BGA :" at 187.225,73.62 h3
  text "Bottom Solder" at 130.564,71.475 h2
  text "Solder Resist" at 146.732,71.475 h2
  text "0.025mm" at 161.266,71.475 h2
  text "3.5" at 173.202,71.475 h2
  text "TRACKS : 0.090mm           / GAPS : 0.090mm" at 187.225,67.87 h3
  text "Bottom Overlay" at 130.564,67.475 h2
  text "Symbol" at 108.265,-10.258 h2.4
  text "Count" at 117.653,-10.258 h2.4
  text "Hole Size" at 127.378,-10.258 h2.4
  text "Plated" at 138.78,-10.258 h2.4
  text "Hole Type" at 147.023,-10.258 h2.4
  text "Drill Layer Pair" at 159.023,-10.258 h2.4
  text "Via/Pad" at 181.752,-10.258 h2.4
  text "Pad Shape" at 191.584,-10.258 h2.4
  text "Hole Length" at 204.429,-10.258 h2.4
  text "381" at 117.653,-14.395 h2
  text "0.200mm" at 127.378,-14.395 h2
  text "PTH" at 138.78,-14.395 h2
  text "Round" at 147.023,-14.395 h2
  text "Top Layer - Bottom Layer" at 159.023,-14.395 h2
  text "Via" at 181.752,-14.395 h2
  text "Rounded" at 191.584,-14.395 h2
  text "-" at 204.429,-14.395 h2
  text "D" at 107.477,-14.649 h1.84
  text "147" at 117.653,-18.533 h2
  text "0.250mm" at 127.378,-18.533 h2
  text "PTH" at 138.78,-18.533 h2
  text "Round" at 147.023,-18.533 h2
  text "Top Layer - Bottom Layer" at 159.023,-18.533 h2
  text "Via" at 181.752,-18.533 h2
  text "Rounded" at 191.584,-18.533 h2
  text "-" at 204.429,-18.533 h2
  text "256" at 117.653,-22.67 h2
  text "0.350mm" at 127.378,-22.67 h2
  text "PTH" at 138.78,-22.67 h2
  text "Round" at 147.023,-22.67 h2
  text "Top Layer - Bottom Layer" at 159.023,-22.67 h2
  text "Via" at 181.752,-22.67 h2
  text "Rounded" at 191.584,-22.67 h2
  text "-" at 204.429,-22.67 h2
  text "C" at 107.477,-22.924 h1.84
  text "2" at 117.653,-26.807 h2
  text "0.500mm" at 127.378,-26.807 h2
  text "PTH" at 138.78,-26.807 h2
  text "Round" at 147.023,-26.807 h2
  text "Top Layer - Bottom Layer" at 159.023,-26.807 h2
  text "Pad" at 181.752,-26.807 h2
  text "Rounded" at 191.584,-26.807 h2
  text "-" at 204.429,-26.807 h2
  text "786 Total" at 117.653,-30.945 h2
